VERSION 5.8 ;
BUSBITCHARS "[]" ;
DIVIDERCHAR "/" ;
UNITS
    DATABASE MICRONS 1000 ;
END UNITS

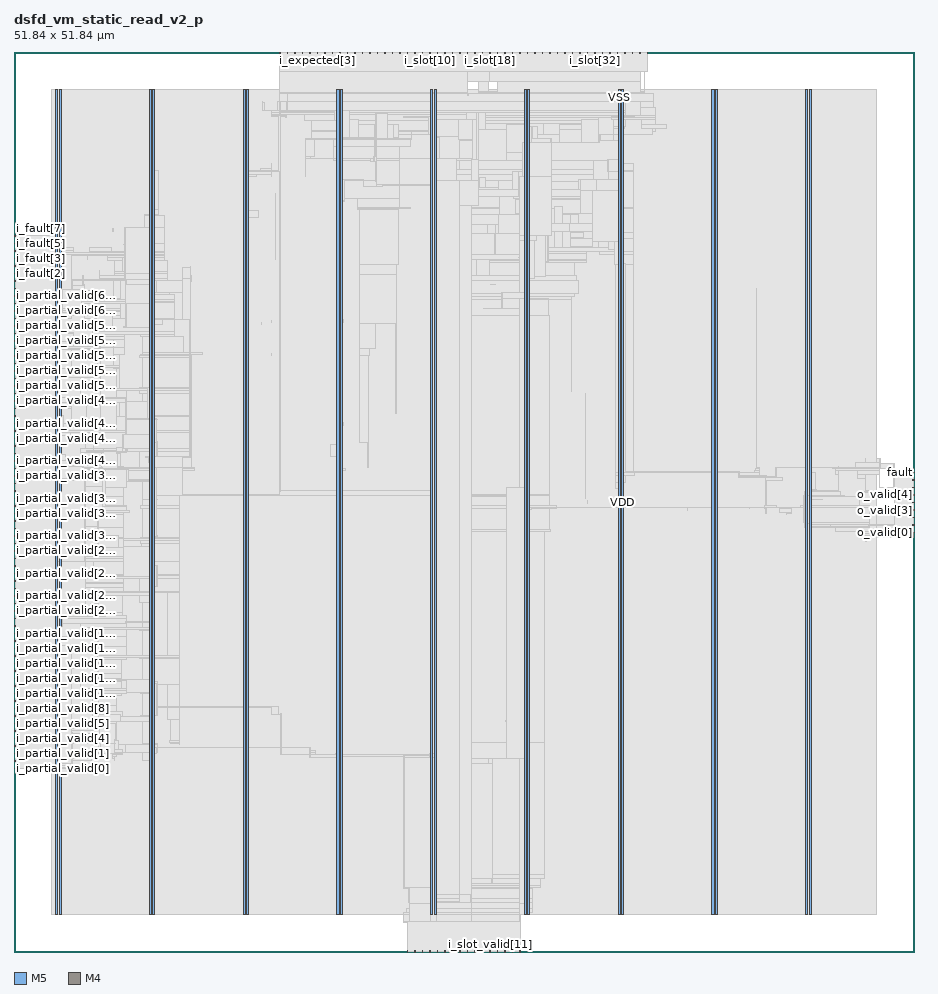
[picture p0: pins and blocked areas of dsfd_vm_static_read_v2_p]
MACRO dsfd_vm_static_read_v2_p
  FOREIGN dsfd_vm_static_read_v2_p 0 0 ;
  CLASS BLOCK ;
  SIZE 51.84 BY 51.84 ;
  PIN ck
    DIRECTION INPUT ;
    USE SIGNAL ;
    PORT
      LAYER M5 ;
        RECT  15.312 51.756 15.336 51.84 ;
    END
  END ck
  PIN fault
    DIRECTION OUTPUT ;
    USE SIGNAL ;
    PORT
      LAYER M4 ;
        RECT  51.756 27.6 51.84 27.624 ;
    END
  END fault
  PIN i_expected[0]
    DIRECTION INPUT ;
    USE SIGNAL ;
    PORT
      LAYER M5 ;
        RECT  16.176 51.756 16.2 51.84 ;
    END
  END i_expected[0]
  PIN i_expected[1]
    DIRECTION INPUT ;
    USE SIGNAL ;
    PORT
      LAYER M5 ;
        RECT  16.608 51.756 16.632 51.84 ;
    END
  END i_expected[1]
  PIN i_expected[2]
    DIRECTION INPUT ;
    USE SIGNAL ;
    PORT
      LAYER M5 ;
        RECT  17.04 51.756 17.064 51.84 ;
    END
  END i_expected[2]
  PIN i_expected[3]
    DIRECTION INPUT ;
    USE SIGNAL ;
    PORT
      LAYER M5 ;
        RECT  17.472 51.756 17.496 51.84 ;
    END
  END i_expected[3]
  PIN i_expected[4]
    DIRECTION INPUT ;
    USE SIGNAL ;
    PORT
      LAYER M5 ;
        RECT  17.904 51.756 17.928 51.84 ;
    END
  END i_expected[4]
  PIN i_expected[5]
    DIRECTION INPUT ;
    USE SIGNAL ;
    PORT
      LAYER M5 ;
        RECT  18.336 51.756 18.36 51.84 ;
    END
  END i_expected[5]
  PIN i_expected[6]
    DIRECTION INPUT ;
    USE SIGNAL ;
    PORT
      LAYER M5 ;
        RECT  18.768 51.756 18.792 51.84 ;
    END
  END i_expected[6]
  PIN i_expected[7]
    DIRECTION INPUT ;
    USE SIGNAL ;
    PORT
      LAYER M5 ;
        RECT  19.2 51.756 19.224 51.84 ;
    END
  END i_expected[7]
  PIN i_fault[0]
    DIRECTION INPUT ;
    USE SIGNAL ;
    PORT
      LAYER M4 ;
        RECT  0 38.208 0.084 38.232 ;
    END
  END i_fault[0]
  PIN i_fault[1]
    DIRECTION INPUT ;
    USE SIGNAL ;
    PORT
      LAYER M4 ;
        RECT  0 38.64 0.084 38.664 ;
    END
  END i_fault[1]
  PIN i_fault[2]
    DIRECTION INPUT ;
    USE SIGNAL ;
    PORT
      LAYER M4 ;
        RECT  0 39.072 0.084 39.096 ;
    END
  END i_fault[2]
  PIN i_fault[3]
    DIRECTION INPUT ;
    USE SIGNAL ;
    PORT
      LAYER M4 ;
        RECT  0 39.504 0.084 39.528 ;
    END
  END i_fault[3]
  PIN i_fault[4]
    DIRECTION INPUT ;
    USE SIGNAL ;
    PORT
      LAYER M4 ;
        RECT  0 39.936 0.084 39.96 ;
    END
  END i_fault[4]
  PIN i_fault[5]
    DIRECTION INPUT ;
    USE SIGNAL ;
    PORT
      LAYER M4 ;
        RECT  0 40.368 0.084 40.392 ;
    END
  END i_fault[5]
  PIN i_fault[6]
    DIRECTION INPUT ;
    USE SIGNAL ;
    PORT
      LAYER M4 ;
        RECT  0 40.8 0.084 40.824 ;
    END
  END i_fault[6]
  PIN i_fault[7]
    DIRECTION INPUT ;
    USE SIGNAL ;
    PORT
      LAYER M4 ;
        RECT  0 41.232 0.084 41.256 ;
    END
  END i_fault[7]
  PIN i_partial_valid[0]
    DIRECTION INPUT ;
    USE SIGNAL ;
    PORT
      LAYER M4 ;
        RECT  0 10.56 0.084 10.584 ;
    END
  END i_partial_valid[0]
  PIN i_partial_valid[10]
    DIRECTION INPUT ;
    USE SIGNAL ;
    PORT
      LAYER M4 ;
        RECT  0 14.88 0.084 14.904 ;
    END
  END i_partial_valid[10]
  PIN i_partial_valid[11]
    DIRECTION INPUT ;
    USE SIGNAL ;
    PORT
      LAYER M4 ;
        RECT  0 15.312 0.084 15.336 ;
    END
  END i_partial_valid[11]
  PIN i_partial_valid[12]
    DIRECTION INPUT ;
    USE SIGNAL ;
    PORT
      LAYER M4 ;
        RECT  0 15.744 0.084 15.768 ;
    END
  END i_partial_valid[12]
  PIN i_partial_valid[13]
    DIRECTION INPUT ;
    USE SIGNAL ;
    PORT
      LAYER M4 ;
        RECT  0 16.176 0.084 16.2 ;
    END
  END i_partial_valid[13]
  PIN i_partial_valid[14]
    DIRECTION INPUT ;
    USE SIGNAL ;
    PORT
      LAYER M4 ;
        RECT  0 16.608 0.084 16.632 ;
    END
  END i_partial_valid[14]
  PIN i_partial_valid[15]
    DIRECTION INPUT ;
    USE SIGNAL ;
    PORT
      LAYER M4 ;
        RECT  0 17.04 0.084 17.064 ;
    END
  END i_partial_valid[15]
  PIN i_partial_valid[16]
    DIRECTION INPUT ;
    USE SIGNAL ;
    PORT
      LAYER M4 ;
        RECT  0 17.472 0.084 17.496 ;
    END
  END i_partial_valid[16]
  PIN i_partial_valid[17]
    DIRECTION INPUT ;
    USE SIGNAL ;
    PORT
      LAYER M4 ;
        RECT  0 17.904 0.084 17.928 ;
    END
  END i_partial_valid[17]
  PIN i_partial_valid[18]
    DIRECTION INPUT ;
    USE SIGNAL ;
    PORT
      LAYER M4 ;
        RECT  0 18.336 0.084 18.36 ;
    END
  END i_partial_valid[18]
  PIN i_partial_valid[19]
    DIRECTION INPUT ;
    USE SIGNAL ;
    PORT
      LAYER M4 ;
        RECT  0 18.768 0.084 18.792 ;
    END
  END i_partial_valid[19]
  PIN i_partial_valid[1]
    DIRECTION INPUT ;
    USE SIGNAL ;
    PORT
      LAYER M4 ;
        RECT  0 10.992 0.084 11.016 ;
    END
  END i_partial_valid[1]
  PIN i_partial_valid[20]
    DIRECTION INPUT ;
    USE SIGNAL ;
    PORT
      LAYER M4 ;
        RECT  0 19.2 0.084 19.224 ;
    END
  END i_partial_valid[20]
  PIN i_partial_valid[21]
    DIRECTION INPUT ;
    USE SIGNAL ;
    PORT
      LAYER M4 ;
        RECT  0 19.632 0.084 19.656 ;
    END
  END i_partial_valid[21]
  PIN i_partial_valid[22]
    DIRECTION INPUT ;
    USE SIGNAL ;
    PORT
      LAYER M4 ;
        RECT  0 20.064 0.084 20.088 ;
    END
  END i_partial_valid[22]
  PIN i_partial_valid[23]
    DIRECTION INPUT ;
    USE SIGNAL ;
    PORT
      LAYER M4 ;
        RECT  0 20.496 0.084 20.52 ;
    END
  END i_partial_valid[23]
  PIN i_partial_valid[24]
    DIRECTION INPUT ;
    USE SIGNAL ;
    PORT
      LAYER M4 ;
        RECT  0 20.928 0.084 20.952 ;
    END
  END i_partial_valid[24]
  PIN i_partial_valid[25]
    DIRECTION INPUT ;
    USE SIGNAL ;
    PORT
      LAYER M4 ;
        RECT  0 21.36 0.084 21.384 ;
    END
  END i_partial_valid[25]
  PIN i_partial_valid[26]
    DIRECTION INPUT ;
    USE SIGNAL ;
    PORT
      LAYER M4 ;
        RECT  0 21.792 0.084 21.816 ;
    END
  END i_partial_valid[26]
  PIN i_partial_valid[27]
    DIRECTION INPUT ;
    USE SIGNAL ;
    PORT
      LAYER M4 ;
        RECT  0 22.224 0.084 22.248 ;
    END
  END i_partial_valid[27]
  PIN i_partial_valid[28]
    DIRECTION INPUT ;
    USE SIGNAL ;
    PORT
      LAYER M4 ;
        RECT  0 22.656 0.084 22.68 ;
    END
  END i_partial_valid[28]
  PIN i_partial_valid[29]
    DIRECTION INPUT ;
    USE SIGNAL ;
    PORT
      LAYER M4 ;
        RECT  0 23.088 0.084 23.112 ;
    END
  END i_partial_valid[29]
  PIN i_partial_valid[2]
    DIRECTION INPUT ;
    USE SIGNAL ;
    PORT
      LAYER M4 ;
        RECT  0 11.424 0.084 11.448 ;
    END
  END i_partial_valid[2]
  PIN i_partial_valid[30]
    DIRECTION INPUT ;
    USE SIGNAL ;
    PORT
      LAYER M4 ;
        RECT  0 23.52 0.084 23.544 ;
    END
  END i_partial_valid[30]
  PIN i_partial_valid[31]
    DIRECTION INPUT ;
    USE SIGNAL ;
    PORT
      LAYER M4 ;
        RECT  0 23.952 0.084 23.976 ;
    END
  END i_partial_valid[31]
  PIN i_partial_valid[32]
    DIRECTION INPUT ;
    USE SIGNAL ;
    PORT
      LAYER M4 ;
        RECT  0 24.384 0.084 24.408 ;
    END
  END i_partial_valid[32]
  PIN i_partial_valid[33]
    DIRECTION INPUT ;
    USE SIGNAL ;
    PORT
      LAYER M4 ;
        RECT  0 24.816 0.084 24.84 ;
    END
  END i_partial_valid[33]
  PIN i_partial_valid[34]
    DIRECTION INPUT ;
    USE SIGNAL ;
    PORT
      LAYER M4 ;
        RECT  0 25.248 0.084 25.272 ;
    END
  END i_partial_valid[34]
  PIN i_partial_valid[35]
    DIRECTION INPUT ;
    USE SIGNAL ;
    PORT
      LAYER M4 ;
        RECT  0 25.68 0.084 25.704 ;
    END
  END i_partial_valid[35]
  PIN i_partial_valid[36]
    DIRECTION INPUT ;
    USE SIGNAL ;
    PORT
      LAYER M4 ;
        RECT  0 26.112 0.084 26.136 ;
    END
  END i_partial_valid[36]
  PIN i_partial_valid[37]
    DIRECTION INPUT ;
    USE SIGNAL ;
    PORT
      LAYER M4 ;
        RECT  0 26.544 0.084 26.568 ;
    END
  END i_partial_valid[37]
  PIN i_partial_valid[38]
    DIRECTION INPUT ;
    USE SIGNAL ;
    PORT
      LAYER M4 ;
        RECT  0 26.976 0.084 27 ;
    END
  END i_partial_valid[38]
  PIN i_partial_valid[39]
    DIRECTION INPUT ;
    USE SIGNAL ;
    PORT
      LAYER M4 ;
        RECT  0 27.408 0.084 27.432 ;
    END
  END i_partial_valid[39]
  PIN i_partial_valid[3]
    DIRECTION INPUT ;
    USE SIGNAL ;
    PORT
      LAYER M4 ;
        RECT  0 11.856 0.084 11.88 ;
    END
  END i_partial_valid[3]
  PIN i_partial_valid[40]
    DIRECTION INPUT ;
    USE SIGNAL ;
    PORT
      LAYER M4 ;
        RECT  0 27.84 0.084 27.864 ;
    END
  END i_partial_valid[40]
  PIN i_partial_valid[41]
    DIRECTION INPUT ;
    USE SIGNAL ;
    PORT
      LAYER M4 ;
        RECT  0 28.272 0.084 28.296 ;
    END
  END i_partial_valid[41]
  PIN i_partial_valid[42]
    DIRECTION INPUT ;
    USE SIGNAL ;
    PORT
      LAYER M4 ;
        RECT  0 28.704 0.084 28.728 ;
    END
  END i_partial_valid[42]
  PIN i_partial_valid[43]
    DIRECTION INPUT ;
    USE SIGNAL ;
    PORT
      LAYER M4 ;
        RECT  0 29.136 0.084 29.16 ;
    END
  END i_partial_valid[43]
  PIN i_partial_valid[44]
    DIRECTION INPUT ;
    USE SIGNAL ;
    PORT
      LAYER M4 ;
        RECT  0 29.568 0.084 29.592 ;
    END
  END i_partial_valid[44]
  PIN i_partial_valid[45]
    DIRECTION INPUT ;
    USE SIGNAL ;
    PORT
      LAYER M4 ;
        RECT  0 30 0.084 30.024 ;
    END
  END i_partial_valid[45]
  PIN i_partial_valid[46]
    DIRECTION INPUT ;
    USE SIGNAL ;
    PORT
      LAYER M4 ;
        RECT  0 30.432 0.084 30.456 ;
    END
  END i_partial_valid[46]
  PIN i_partial_valid[47]
    DIRECTION INPUT ;
    USE SIGNAL ;
    PORT
      LAYER M4 ;
        RECT  0 30.864 0.084 30.888 ;
    END
  END i_partial_valid[47]
  PIN i_partial_valid[48]
    DIRECTION INPUT ;
    USE SIGNAL ;
    PORT
      LAYER M4 ;
        RECT  0 31.296 0.084 31.32 ;
    END
  END i_partial_valid[48]
  PIN i_partial_valid[49]
    DIRECTION INPUT ;
    USE SIGNAL ;
    PORT
      LAYER M4 ;
        RECT  0 31.728 0.084 31.752 ;
    END
  END i_partial_valid[49]
  PIN i_partial_valid[4]
    DIRECTION INPUT ;
    USE SIGNAL ;
    PORT
      LAYER M4 ;
        RECT  0 12.288 0.084 12.312 ;
    END
  END i_partial_valid[4]
  PIN i_partial_valid[50]
    DIRECTION INPUT ;
    USE SIGNAL ;
    PORT
      LAYER M4 ;
        RECT  0 32.16 0.084 32.184 ;
    END
  END i_partial_valid[50]
  PIN i_partial_valid[51]
    DIRECTION INPUT ;
    USE SIGNAL ;
    PORT
      LAYER M4 ;
        RECT  0 32.592 0.084 32.616 ;
    END
  END i_partial_valid[51]
  PIN i_partial_valid[52]
    DIRECTION INPUT ;
    USE SIGNAL ;
    PORT
      LAYER M4 ;
        RECT  0 33.024 0.084 33.048 ;
    END
  END i_partial_valid[52]
  PIN i_partial_valid[53]
    DIRECTION INPUT ;
    USE SIGNAL ;
    PORT
      LAYER M4 ;
        RECT  0 33.456 0.084 33.48 ;
    END
  END i_partial_valid[53]
  PIN i_partial_valid[54]
    DIRECTION INPUT ;
    USE SIGNAL ;
    PORT
      LAYER M4 ;
        RECT  0 33.888 0.084 33.912 ;
    END
  END i_partial_valid[54]
  PIN i_partial_valid[55]
    DIRECTION INPUT ;
    USE SIGNAL ;
    PORT
      LAYER M4 ;
        RECT  0 34.32 0.084 34.344 ;
    END
  END i_partial_valid[55]
  PIN i_partial_valid[56]
    DIRECTION INPUT ;
    USE SIGNAL ;
    PORT
      LAYER M4 ;
        RECT  0 34.752 0.084 34.776 ;
    END
  END i_partial_valid[56]
  PIN i_partial_valid[57]
    DIRECTION INPUT ;
    USE SIGNAL ;
    PORT
      LAYER M4 ;
        RECT  0 35.184 0.084 35.208 ;
    END
  END i_partial_valid[57]
  PIN i_partial_valid[58]
    DIRECTION INPUT ;
    USE SIGNAL ;
    PORT
      LAYER M4 ;
        RECT  0 35.616 0.084 35.64 ;
    END
  END i_partial_valid[58]
  PIN i_partial_valid[59]
    DIRECTION INPUT ;
    USE SIGNAL ;
    PORT
      LAYER M4 ;
        RECT  0 36.048 0.084 36.072 ;
    END
  END i_partial_valid[59]
  PIN i_partial_valid[5]
    DIRECTION INPUT ;
    USE SIGNAL ;
    PORT
      LAYER M4 ;
        RECT  0 12.72 0.084 12.744 ;
    END
  END i_partial_valid[5]
  PIN i_partial_valid[60]
    DIRECTION INPUT ;
    USE SIGNAL ;
    PORT
      LAYER M4 ;
        RECT  0 36.48 0.084 36.504 ;
    END
  END i_partial_valid[60]
  PIN i_partial_valid[61]
    DIRECTION INPUT ;
    USE SIGNAL ;
    PORT
      LAYER M4 ;
        RECT  0 36.912 0.084 36.936 ;
    END
  END i_partial_valid[61]
  PIN i_partial_valid[62]
    DIRECTION INPUT ;
    USE SIGNAL ;
    PORT
      LAYER M4 ;
        RECT  0 37.344 0.084 37.368 ;
    END
  END i_partial_valid[62]
  PIN i_partial_valid[63]
    DIRECTION INPUT ;
    USE SIGNAL ;
    PORT
      LAYER M4 ;
        RECT  0 37.776 0.084 37.8 ;
    END
  END i_partial_valid[63]
  PIN i_partial_valid[6]
    DIRECTION INPUT ;
    USE SIGNAL ;
    PORT
      LAYER M4 ;
        RECT  0 13.152 0.084 13.176 ;
    END
  END i_partial_valid[6]
  PIN i_partial_valid[7]
    DIRECTION INPUT ;
    USE SIGNAL ;
    PORT
      LAYER M4 ;
        RECT  0 13.584 0.084 13.608 ;
    END
  END i_partial_valid[7]
  PIN i_partial_valid[8]
    DIRECTION INPUT ;
    USE SIGNAL ;
    PORT
      LAYER M4 ;
        RECT  0 14.016 0.084 14.04 ;
    END
  END i_partial_valid[8]
  PIN i_partial_valid[9]
    DIRECTION INPUT ;
    USE SIGNAL ;
    PORT
      LAYER M4 ;
        RECT  0 14.448 0.084 14.472 ;
    END
  END i_partial_valid[9]
  PIN i_slot[0]
    DIRECTION INPUT ;
    USE SIGNAL ;
    PORT
      LAYER M5 ;
        RECT  19.632 51.756 19.656 51.84 ;
    END
  END i_slot[0]
  PIN i_slot[10]
    DIRECTION INPUT ;
    USE SIGNAL ;
    PORT
      LAYER M5 ;
        RECT  23.952 51.756 23.976 51.84 ;
    END
  END i_slot[10]
  PIN i_slot[11]
    DIRECTION INPUT ;
    USE SIGNAL ;
    PORT
      LAYER M5 ;
        RECT  24.384 51.756 24.408 51.84 ;
    END
  END i_slot[11]
  PIN i_slot[12]
    DIRECTION INPUT ;
    USE SIGNAL ;
    PORT
      LAYER M5 ;
        RECT  24.816 51.756 24.84 51.84 ;
    END
  END i_slot[12]
  PIN i_slot[13]
    DIRECTION INPUT ;
    USE SIGNAL ;
    PORT
      LAYER M5 ;
        RECT  25.248 51.756 25.272 51.84 ;
    END
  END i_slot[13]
  PIN i_slot[14]
    DIRECTION INPUT ;
    USE SIGNAL ;
    PORT
      LAYER M5 ;
        RECT  25.68 51.756 25.704 51.84 ;
    END
  END i_slot[14]
  PIN i_slot[15]
    DIRECTION INPUT ;
    USE SIGNAL ;
    PORT
      LAYER M5 ;
        RECT  26.112 51.756 26.136 51.84 ;
    END
  END i_slot[15]
  PIN i_slot[16]
    DIRECTION INPUT ;
    USE SIGNAL ;
    PORT
      LAYER M5 ;
        RECT  26.544 51.756 26.568 51.84 ;
    END
  END i_slot[16]
  PIN i_slot[17]
    DIRECTION INPUT ;
    USE SIGNAL ;
    PORT
      LAYER M5 ;
        RECT  26.976 51.756 27 51.84 ;
    END
  END i_slot[17]
  PIN i_slot[18]
    DIRECTION INPUT ;
    USE SIGNAL ;
    PORT
      LAYER M5 ;
        RECT  27.408 51.756 27.432 51.84 ;
    END
  END i_slot[18]
  PIN i_slot[19]
    DIRECTION INPUT ;
    USE SIGNAL ;
    PORT
      LAYER M5 ;
        RECT  27.84 51.756 27.864 51.84 ;
    END
  END i_slot[19]
  PIN i_slot[1]
    DIRECTION INPUT ;
    USE SIGNAL ;
    PORT
      LAYER M5 ;
        RECT  20.064 51.756 20.088 51.84 ;
    END
  END i_slot[1]
  PIN i_slot[20]
    DIRECTION INPUT ;
    USE SIGNAL ;
    PORT
      LAYER M5 ;
        RECT  28.272 51.756 28.296 51.84 ;
    END
  END i_slot[20]
  PIN i_slot[21]
    DIRECTION INPUT ;
    USE SIGNAL ;
    PORT
      LAYER M5 ;
        RECT  28.704 51.756 28.728 51.84 ;
    END
  END i_slot[21]
  PIN i_slot[22]
    DIRECTION INPUT ;
    USE SIGNAL ;
    PORT
      LAYER M5 ;
        RECT  29.136 51.756 29.16 51.84 ;
    END
  END i_slot[22]
  PIN i_slot[23]
    DIRECTION INPUT ;
    USE SIGNAL ;
    PORT
      LAYER M5 ;
        RECT  29.568 51.756 29.592 51.84 ;
    END
  END i_slot[23]
  PIN i_slot[24]
    DIRECTION INPUT ;
    USE SIGNAL ;
    PORT
      LAYER M5 ;
        RECT  30 51.756 30.024 51.84 ;
    END
  END i_slot[24]
  PIN i_slot[25]
    DIRECTION INPUT ;
    USE SIGNAL ;
    PORT
      LAYER M5 ;
        RECT  30.432 51.756 30.456 51.84 ;
    END
  END i_slot[25]
  PIN i_slot[26]
    DIRECTION INPUT ;
    USE SIGNAL ;
    PORT
      LAYER M5 ;
        RECT  30.864 51.756 30.888 51.84 ;
    END
  END i_slot[26]
  PIN i_slot[27]
    DIRECTION INPUT ;
    USE SIGNAL ;
    PORT
      LAYER M5 ;
        RECT  31.296 51.756 31.32 51.84 ;
    END
  END i_slot[27]
  PIN i_slot[28]
    DIRECTION INPUT ;
    USE SIGNAL ;
    PORT
      LAYER M5 ;
        RECT  31.728 51.756 31.752 51.84 ;
    END
  END i_slot[28]
  PIN i_slot[29]
    DIRECTION INPUT ;
    USE SIGNAL ;
    PORT
      LAYER M5 ;
        RECT  32.16 51.756 32.184 51.84 ;
    END
  END i_slot[29]
  PIN i_slot[2]
    DIRECTION INPUT ;
    USE SIGNAL ;
    PORT
      LAYER M5 ;
        RECT  20.496 51.756 20.52 51.84 ;
    END
  END i_slot[2]
  PIN i_slot[30]
    DIRECTION INPUT ;
    USE SIGNAL ;
    PORT
      LAYER M5 ;
        RECT  32.592 51.756 32.616 51.84 ;
    END
  END i_slot[30]
  PIN i_slot[31]
    DIRECTION INPUT ;
    USE SIGNAL ;
    PORT
      LAYER M5 ;
        RECT  33.024 51.756 33.048 51.84 ;
    END
  END i_slot[31]
  PIN i_slot[32]
    DIRECTION INPUT ;
    USE SIGNAL ;
    PORT
      LAYER M5 ;
        RECT  33.456 51.756 33.48 51.84 ;
    END
  END i_slot[32]
  PIN i_slot[33]
    DIRECTION INPUT ;
    USE SIGNAL ;
    PORT
      LAYER M5 ;
        RECT  33.888 51.756 33.912 51.84 ;
    END
  END i_slot[33]
  PIN i_slot[34]
    DIRECTION INPUT ;
    USE SIGNAL ;
    PORT
      LAYER M5 ;
        RECT  34.32 51.756 34.344 51.84 ;
    END
  END i_slot[34]
  PIN i_slot[35]
    DIRECTION INPUT ;
    USE SIGNAL ;
    PORT
      LAYER M5 ;
        RECT  34.752 51.756 34.776 51.84 ;
    END
  END i_slot[35]
  PIN i_slot[36]
    DIRECTION INPUT ;
    USE SIGNAL ;
    PORT
      LAYER M5 ;
        RECT  35.184 51.756 35.208 51.84 ;
    END
  END i_slot[36]
  PIN i_slot[37]
    DIRECTION INPUT ;
    USE SIGNAL ;
    PORT
      LAYER M5 ;
        RECT  35.616 51.756 35.64 51.84 ;
    END
  END i_slot[37]
  PIN i_slot[38]
    DIRECTION INPUT ;
    USE SIGNAL ;
    PORT
      LAYER M5 ;
        RECT  36.048 51.756 36.072 51.84 ;
    END
  END i_slot[38]
  PIN i_slot[39]
    DIRECTION INPUT ;
    USE SIGNAL ;
    PORT
      LAYER M5 ;
        RECT  36.48 51.756 36.504 51.84 ;
    END
  END i_slot[39]
  PIN i_slot[3]
    DIRECTION INPUT ;
    USE SIGNAL ;
    PORT
      LAYER M5 ;
        RECT  20.928 51.756 20.952 51.84 ;
    END
  END i_slot[3]
  PIN i_slot[4]
    DIRECTION INPUT ;
    USE SIGNAL ;
    PORT
      LAYER M5 ;
        RECT  21.36 51.756 21.384 51.84 ;
    END
  END i_slot[4]
  PIN i_slot[5]
    DIRECTION INPUT ;
    USE SIGNAL ;
    PORT
      LAYER M5 ;
        RECT  21.792 51.756 21.816 51.84 ;
    END
  END i_slot[5]
  PIN i_slot[6]
    DIRECTION INPUT ;
    USE SIGNAL ;
    PORT
      LAYER M5 ;
        RECT  22.224 51.756 22.248 51.84 ;
    END
  END i_slot[6]
  PIN i_slot[7]
    DIRECTION INPUT ;
    USE SIGNAL ;
    PORT
      LAYER M5 ;
        RECT  22.656 51.756 22.68 51.84 ;
    END
  END i_slot[7]
  PIN i_slot[8]
    DIRECTION INPUT ;
    USE SIGNAL ;
    PORT
      LAYER M5 ;
        RECT  23.088 51.756 23.112 51.84 ;
    END
  END i_slot[8]
  PIN i_slot[9]
    DIRECTION INPUT ;
    USE SIGNAL ;
    PORT
      LAYER M5 ;
        RECT  23.52 51.756 23.544 51.84 ;
    END
  END i_slot[9]
  PIN i_slot_valid[0]
    DIRECTION INPUT ;
    USE SIGNAL ;
    PORT
      LAYER M5 ;
        RECT  22.656 0 22.68 0.084 ;
    END
  END i_slot_valid[0]
  PIN i_slot_valid[10]
    DIRECTION INPUT ;
    USE SIGNAL ;
    PORT
      LAYER M5 ;
        RECT  26.976 0 27 0.084 ;
    END
  END i_slot_valid[10]
  PIN i_slot_valid[11]
    DIRECTION INPUT ;
    USE SIGNAL ;
    PORT
      LAYER M5 ;
        RECT  27.408 0 27.432 0.084 ;
    END
  END i_slot_valid[11]
  PIN i_slot_valid[12]
    DIRECTION INPUT ;
    USE SIGNAL ;
    PORT
      LAYER M5 ;
        RECT  27.84 0 27.864 0.084 ;
    END
  END i_slot_valid[12]
  PIN i_slot_valid[13]
    DIRECTION INPUT ;
    USE SIGNAL ;
    PORT
      LAYER M5 ;
        RECT  28.272 0 28.296 0.084 ;
    END
  END i_slot_valid[13]
  PIN i_slot_valid[14]
    DIRECTION INPUT ;
    USE SIGNAL ;
    PORT
      LAYER M5 ;
        RECT  28.704 0 28.728 0.084 ;
    END
  END i_slot_valid[14]
  PIN i_slot_valid[15]
    DIRECTION INPUT ;
    USE SIGNAL ;
    PORT
      LAYER M5 ;
        RECT  29.136 0 29.16 0.084 ;
    END
  END i_slot_valid[15]
  PIN i_slot_valid[1]
    DIRECTION INPUT ;
    USE SIGNAL ;
    PORT
      LAYER M5 ;
        RECT  23.088 0 23.112 0.084 ;
    END
  END i_slot_valid[1]
  PIN i_slot_valid[2]
    DIRECTION INPUT ;
    USE SIGNAL ;
    PORT
      LAYER M5 ;
        RECT  23.52 0 23.544 0.084 ;
    END
  END i_slot_valid[2]
  PIN i_slot_valid[3]
    DIRECTION INPUT ;
    USE SIGNAL ;
    PORT
      LAYER M5 ;
        RECT  23.952 0 23.976 0.084 ;
    END
  END i_slot_valid[3]
  PIN i_slot_valid[4]
    DIRECTION INPUT ;
    USE SIGNAL ;
    PORT
      LAYER M5 ;
        RECT  24.384 0 24.408 0.084 ;
    END
  END i_slot_valid[4]
  PIN i_slot_valid[5]
    DIRECTION INPUT ;
    USE SIGNAL ;
    PORT
      LAYER M5 ;
        RECT  24.816 0 24.84 0.084 ;
    END
  END i_slot_valid[5]
  PIN i_slot_valid[6]
    DIRECTION INPUT ;
    USE SIGNAL ;
    PORT
      LAYER M5 ;
        RECT  25.248 0 25.272 0.084 ;
    END
  END i_slot_valid[6]
  PIN i_slot_valid[7]
    DIRECTION INPUT ;
    USE SIGNAL ;
    PORT
      LAYER M5 ;
        RECT  25.68 0 25.704 0.084 ;
    END
  END i_slot_valid[7]
  PIN i_slot_valid[8]
    DIRECTION INPUT ;
    USE SIGNAL ;
    PORT
      LAYER M5 ;
        RECT  26.112 0 26.136 0.084 ;
    END
  END i_slot_valid[8]
  PIN i_slot_valid[9]
    DIRECTION INPUT ;
    USE SIGNAL ;
    PORT
      LAYER M5 ;
        RECT  26.544 0 26.568 0.084 ;
    END
  END i_slot_valid[9]
  PIN o_valid[0]
    DIRECTION OUTPUT ;
    USE SIGNAL ;
    PORT
      LAYER M4 ;
        RECT  51.756 24.144 51.84 24.168 ;
    END
  END o_valid[0]
  PIN o_valid[1]
    DIRECTION OUTPUT ;
    USE SIGNAL ;
    PORT
      LAYER M4 ;
        RECT  51.756 24.576 51.84 24.6 ;
    END
  END o_valid[1]
  PIN o_valid[2]
    DIRECTION OUTPUT ;
    USE SIGNAL ;
    PORT
      LAYER M4 ;
        RECT  51.756 25.008 51.84 25.032 ;
    END
  END o_valid[2]
  PIN o_valid[3]
    DIRECTION OUTPUT ;
    USE SIGNAL ;
    PORT
      LAYER M4 ;
        RECT  51.756 25.44 51.84 25.464 ;
    END
  END o_valid[3]
  PIN o_valid[4]
    DIRECTION OUTPUT ;
    USE SIGNAL ;
    PORT
      LAYER M4 ;
        RECT  51.756 25.872 51.84 25.896 ;
    END
  END o_valid[4]
  PIN o_valid[5]
    DIRECTION OUTPUT ;
    USE SIGNAL ;
    PORT
      LAYER M4 ;
        RECT  51.756 26.304 51.84 26.328 ;
    END
  END o_valid[5]
  PIN o_valid[6]
    DIRECTION OUTPUT ;
    USE SIGNAL ;
    PORT
      LAYER M4 ;
        RECT  51.756 26.736 51.84 26.76 ;
    END
  END o_valid[6]
  PIN o_valid[7]
    DIRECTION OUTPUT ;
    USE SIGNAL ;
    PORT
      LAYER M4 ;
        RECT  51.756 27.168 51.84 27.192 ;
    END
  END o_valid[7]
  PIN rst_n
    DIRECTION INPUT ;
    USE SIGNAL ;
    PORT
      LAYER M5 ;
        RECT  15.744 51.756 15.768 51.84 ;
    END
  END rst_n
  PIN VDD
    DIRECTION INOUT ;
    USE POWER ;
    PORT
      LAYER M5 ;
        RECT  45.792 2.151 45.912 49.689 ;
        RECT  40.392 2.151 40.512 49.689 ;
        RECT  34.992 2.151 35.112 49.689 ;
        RECT  29.592 2.151 29.712 49.689 ;
        RECT  24.192 2.151 24.312 49.689 ;
        RECT  18.792 2.151 18.912 49.689 ;
        RECT  13.392 2.151 13.512 49.689 ;
        RECT  7.992 2.151 8.112 49.689 ;
        RECT  2.592 2.151 2.712 49.689 ;
    END
  END VDD
  PIN VSS
    DIRECTION INOUT ;
    USE GROUND ;
    PORT
      LAYER M5 ;
        RECT  45.6 2.137 45.72 49.703 ;
        RECT  40.2 2.137 40.32 49.703 ;
        RECT  34.8 2.137 34.92 49.703 ;
        RECT  29.4 2.137 29.52 49.703 ;
        RECT  24 2.137 24.12 49.703 ;
        RECT  18.6 2.137 18.72 49.703 ;
        RECT  13.2 2.137 13.32 49.703 ;
        RECT  7.8 2.137 7.92 49.703 ;
        RECT  2.4 2.137 2.52 49.703 ;
    END
  END VSS
  # OT_OBS_CLOSED layer=M5 d_um=1.536 added=40
  OBS
    LAYER RVTN ;
     RECT  2.16 2.16 49.68 2.295 ;
     RECT  2.16 2.565 49.68 2.835 ;
     RECT  2.16 3.105 49.68 3.375 ;
     RECT  2.16 3.645 49.68 3.915 ;
     RECT  2.16 4.185 49.68 4.455 ;
     RECT  2.16 4.725 49.68 4.995 ;
     RECT  2.16 5.265 49.68 5.535 ;
     RECT  2.16 5.805 49.68 6.075 ;
     RECT  2.16 6.345 49.68 6.615 ;
     RECT  2.16 6.885 49.68 7.155 ;
     RECT  2.16 7.425 49.68 7.695 ;
     RECT  2.16 7.965 49.68 8.235 ;
     RECT  2.16 8.505 49.68 8.775 ;
     RECT  2.16 9.045 49.68 9.315 ;
     RECT  2.16 9.585 49.68 9.855 ;
     RECT  2.16 10.125 49.68 10.395 ;
     RECT  2.16 10.665 49.68 10.935 ;
     RECT  2.16 11.205 49.68 11.475 ;
     RECT  2.16 11.745 49.68 12.015 ;
     RECT  2.16 12.285 49.68 12.555 ;
     RECT  2.16 12.825 49.68 13.095 ;
     RECT  2.16 13.365 49.68 13.635 ;
     RECT  2.16 13.905 49.68 14.175 ;
     RECT  2.16 14.445 49.68 14.715 ;
     RECT  2.16 14.985 49.68 15.255 ;
     RECT  2.16 15.525 49.68 15.795 ;
     RECT  2.16 16.065 49.68 16.335 ;
     RECT  2.16 16.605 49.68 16.875 ;
     RECT  2.16 17.145 49.68 17.415 ;
     RECT  2.16 17.685 49.68 17.955 ;
     RECT  2.16 18.225 49.68 18.495 ;
     RECT  2.16 18.765 49.68 19.035 ;
     RECT  2.16 19.305 49.68 19.575 ;
     RECT  2.16 19.845 49.68 20.115 ;
     RECT  2.16 20.385 49.68 20.655 ;
     RECT  2.16 20.925 49.68 21.195 ;
     RECT  2.16 21.465 49.68 21.735 ;
     RECT  2.16 22.005 49.68 22.275 ;
     RECT  2.16 22.545 49.68 22.815 ;
     RECT  2.16 23.085 49.68 23.355 ;
     RECT  2.16 23.625 49.68 23.895 ;
     RECT  2.16 24.165 49.68 24.435 ;
     RECT  2.16 24.705 49.68 24.975 ;
     RECT  2.16 25.245 49.68 25.515 ;
     RECT  2.16 25.785 49.68 26.055 ;
     RECT  2.16 26.325 49.68 26.595 ;
     RECT  2.16 26.865 49.68 27.135 ;
     RECT  2.16 27.405 49.68 27.675 ;
     RECT  2.16 27.945 49.68 28.215 ;
     RECT  2.16 28.485 49.68 28.755 ;
     RECT  2.16 29.025 49.68 29.295 ;
     RECT  2.16 29.565 49.68 29.835 ;
     RECT  2.16 30.105 49.68 30.375 ;
     RECT  2.16 30.645 49.68 30.915 ;
     RECT  2.16 31.185 49.68 31.455 ;
     RECT  2.16 31.725 49.68 31.995 ;
     RECT  2.16 32.265 49.68 32.535 ;
     RECT  2.16 32.805 49.68 33.075 ;
     RECT  2.16 33.345 49.68 33.615 ;
     RECT  2.16 33.885 49.68 34.155 ;
     RECT  2.16 34.425 49.68 34.695 ;
     RECT  2.16 34.965 49.68 35.235 ;
     RECT  2.16 35.505 49.68 35.775 ;
     RECT  2.16 36.045 49.68 36.315 ;
     RECT  2.16 36.585 49.68 36.855 ;
     RECT  2.16 37.125 49.68 37.395 ;
     RECT  2.16 37.665 49.68 37.935 ;
     RECT  2.16 38.205 49.68 38.475 ;
     RECT  2.16 38.745 49.68 39.015 ;
     RECT  2.16 39.285 49.68 39.555 ;
     RECT  2.16 39.825 49.68 40.095 ;
     RECT  2.16 40.365 49.68 40.635 ;
     RECT  2.16 40.905 49.68 41.175 ;
     RECT  2.16 41.445 49.68 41.715 ;
     RECT  2.16 41.985 49.68 42.255 ;
     RECT  2.16 42.525 49.68 42.795 ;
     RECT  2.16 43.065 49.68 43.335 ;
     RECT  2.16 43.605 49.68 43.875 ;
     RECT  2.16 44.145 49.68 44.415 ;
     RECT  2.16 44.685 49.68 44.955 ;
     RECT  2.16 45.225 49.68 45.495 ;
     RECT  2.16 45.765 49.68 46.035 ;
     RECT  2.16 46.305 49.68 46.575 ;
     RECT  2.16 46.845 49.68 47.115 ;
     RECT  2.16 47.385 49.68 47.655 ;
     RECT  2.16 47.925 49.68 48.195 ;
     RECT  2.16 48.465 49.68 48.735 ;
     RECT  2.16 49.005 49.68 49.275 ;
     RECT  2.16 49.545 49.68 49.68 ;
    LAYER RVTP ;
     RECT  2.16 2.295 49.68 2.565 ;
     RECT  2.16 2.835 49.68 3.105 ;
     RECT  2.16 3.375 49.68 3.645 ;
     RECT  2.16 3.915 49.68 4.185 ;
     RECT  2.16 4.455 49.68 4.725 ;
     RECT  2.16 4.995 49.68 5.265 ;
     RECT  2.16 5.535 49.68 5.805 ;
     RECT  2.16 6.075 49.68 6.345 ;
     RECT  2.16 6.615 49.68 6.885 ;
     RECT  2.16 7.155 49.68 7.425 ;
     RECT  2.16 7.695 49.68 7.965 ;
     RECT  2.16 8.235 49.68 8.505 ;
     RECT  2.16 8.775 49.68 9.045 ;
     RECT  2.16 9.315 49.68 9.585 ;
     RECT  2.16 9.855 49.68 10.125 ;
     RECT  2.16 10.395 49.68 10.665 ;
     RECT  2.16 10.935 49.68 11.205 ;
     RECT  2.16 11.475 49.68 11.745 ;
     RECT  2.16 12.015 49.68 12.285 ;
     RECT  2.16 12.555 49.68 12.825 ;
     RECT  2.16 13.095 49.68 13.365 ;
     RECT  2.16 13.635 49.68 13.905 ;
     RECT  2.16 14.175 49.68 14.445 ;
     RECT  2.16 14.715 49.68 14.985 ;
     RECT  2.16 15.255 49.68 15.525 ;
     RECT  2.16 15.795 49.68 16.065 ;
     RECT  2.16 16.335 49.68 16.605 ;
     RECT  2.16 16.875 49.68 17.145 ;
     RECT  2.16 17.415 49.68 17.685 ;
     RECT  2.16 17.955 49.68 18.225 ;
     RECT  2.16 18.495 49.68 18.765 ;
     RECT  2.16 19.035 49.68 19.305 ;
     RECT  2.16 19.575 49.68 19.845 ;
     RECT  2.16 20.115 49.68 20.385 ;
     RECT  2.16 20.655 49.68 20.925 ;
     RECT  2.16 21.195 49.68 21.465 ;
     RECT  2.16 21.735 49.68 22.005 ;
     RECT  2.16 22.275 49.68 22.545 ;
     RECT  2.16 22.815 49.68 23.085 ;
     RECT  2.16 23.355 49.68 23.625 ;
     RECT  2.16 23.895 49.68 24.165 ;
     RECT  2.16 24.435 49.68 24.705 ;
     RECT  2.16 24.975 49.68 25.245 ;
     RECT  2.16 25.515 49.68 25.785 ;
     RECT  2.16 26.055 49.68 26.325 ;
     RECT  2.16 26.595 49.68 26.865 ;
     RECT  2.16 27.135 49.68 27.405 ;
     RECT  2.16 27.675 49.68 27.945 ;
     RECT  2.16 28.215 49.68 28.485 ;
     RECT  2.16 28.755 49.68 29.025 ;
     RECT  2.16 29.295 49.68 29.565 ;
     RECT  2.16 29.835 49.68 30.105 ;
     RECT  2.16 30.375 49.68 30.645 ;
     RECT  2.16 30.915 49.68 31.185 ;
     RECT  2.16 31.455 49.68 31.725 ;
     RECT  2.16 31.995 49.68 32.265 ;
     RECT  2.16 32.535 49.68 32.805 ;
     RECT  2.16 33.075 49.68 33.345 ;
     RECT  2.16 33.615 49.68 33.885 ;
     RECT  2.16 34.155 49.68 34.425 ;
     RECT  2.16 34.695 49.68 34.965 ;
     RECT  2.16 35.235 49.68 35.505 ;
     RECT  2.16 35.775 49.68 36.045 ;
     RECT  2.16 36.315 49.68 36.585 ;
     RECT  2.16 36.855 49.68 37.125 ;
     RECT  2.16 37.395 49.68 37.665 ;
     RECT  2.16 37.935 49.68 38.205 ;
     RECT  2.16 38.475 49.68 38.745 ;
     RECT  2.16 39.015 49.68 39.285 ;
     RECT  2.16 39.555 49.68 39.825 ;
     RECT  2.16 40.095 49.68 40.365 ;
     RECT  2.16 40.635 49.68 40.905 ;
     RECT  2.16 41.175 49.68 41.445 ;
     RECT  2.16 41.715 49.68 41.985 ;
     RECT  2.16 42.255 49.68 42.525 ;
     RECT  2.16 42.795 49.68 43.065 ;
     RECT  2.16 43.335 49.68 43.605 ;
     RECT  2.16 43.875 49.68 44.145 ;
     RECT  2.16 44.415 49.68 44.685 ;
     RECT  2.16 44.955 49.68 45.225 ;
     RECT  2.16 45.495 49.68 45.765 ;
     RECT  2.16 46.035 49.68 46.305 ;
     RECT  2.16 46.575 49.68 46.845 ;
     RECT  2.16 47.115 49.68 47.385 ;
     RECT  2.16 47.655 49.68 47.925 ;
     RECT  2.16 48.195 49.68 48.465 ;
     RECT  2.16 48.735 49.68 49.005 ;
     RECT  2.16 49.275 49.68 49.545 ;
    LAYER M1 ;
     RECT  2.16 2.151 49.68 49.689 ;
    LAYER M2 ;
     RECT  0.535 22.212 2.16 22.23 ;
     RECT  0.535 23.832 2.16 23.85 ;
     RECT  0.535 27.342 2.16 27.36 ;
     RECT  0.103 32.472 2.16 32.49 ;
     RECT  0.103 38.142 2.16 38.16 ;
     RECT  2.16 2.151 49.68 49.689 ;
     RECT  49.68 27.846 49.883 28.404 ;
     RECT  49.883 27.846 50.675 28.134 ;
     RECT  49.68 26.496 50.711 26.514 ;
     RECT  50.675 28.116 50.711 28.134 ;
     RECT  49.68 23.904 50.747 25.344 ;
     RECT  50.747 24.786 50.783 24.804 ;
    LAYER M3 ;
     RECT  23.94 0.571 23.958 1.723 ;
     RECT  25.668 0.571 25.686 1.723 ;
     RECT  22.428 1.723 29.142 2.143 ;
     RECT  22.428 2.143 29.505 2.255 ;
     RECT  22.608 2.255 29.505 2.263 ;
     RECT  2.415 2.143 2.505 2.413 ;
     RECT  7.815 2.143 7.905 2.413 ;
     RECT  13.215 2.143 13.305 2.413 ;
     RECT  18.615 2.143 18.705 2.413 ;
     RECT  34.815 2.143 34.905 2.413 ;
     RECT  40.215 2.143 40.305 2.413 ;
     RECT  45.615 2.143 45.705 2.413 ;
     RECT  22.608 2.263 29.862 2.489 ;
     RECT  22.752 2.489 29.862 2.861 ;
     RECT  22.932 2.861 29.862 3.065 ;
     RECT  23.184 3.065 29.862 3.641 ;
     RECT  23.976 3.641 29.862 3.721 ;
     RECT  23.976 3.721 30.33 3.839 ;
     RECT  23.184 3.641 23.202 3.947 ;
     RECT  24.015 3.839 30.33 4.261 ;
     RECT  24.015 4.261 30.546 4.487 ;
     RECT  2.415 2.413 2.697 10.555 ;
     RECT  2.304 10.555 2.697 10.597 ;
     RECT  2.304 10.597 3.294 10.625 ;
     RECT  2.34 10.625 3.294 10.633 ;
     RECT  4.068 10.597 4.086 10.633 ;
     RECT  2.34 10.633 4.086 10.741 ;
     RECT  7.815 2.413 8.097 11.011 ;
     RECT  2.34 10.741 4.482 11.021 ;
     RECT  2.415 11.021 4.482 11.131 ;
     RECT  5.796 11.011 5.814 11.137 ;
     RECT  18.615 2.413 18.897 11.275 ;
     RECT  5.652 11.137 5.814 11.281 ;
     RECT  18.615 11.275 18.918 11.365 ;
     RECT  5.652 11.281 5.886 11.371 ;
     RECT  17.028 11.227 17.046 11.371 ;
     RECT  18.504 11.365 18.918 11.399 ;
     RECT  18.504 11.399 18.897 11.405 ;
     RECT  2.415 11.131 4.842 11.419 ;
     RECT  5.652 11.371 6.246 11.419 ;
     RECT  2.415 11.419 6.246 11.435 ;
     RECT  2.415 11.435 4.95 11.453 ;
     RECT  5.796 11.435 6.246 11.467 ;
     RECT  17.028 11.371 17.37 11.471 ;
     RECT  5.796 11.467 6.462 11.507 ;
     RECT  7.416 11.011 8.097 11.515 ;
     RECT  17.064 11.471 17.37 11.579 ;
     RECT  5.796 11.507 6.246 11.669 ;
     RECT  7.308 11.515 8.097 11.669 ;
     RECT  3.42 11.453 4.95 11.705 ;
     RECT  17.064 11.579 17.082 11.789 ;
     RECT  2.415 11.453 2.697 11.851 ;
     RECT  7.416 11.669 8.097 11.911 ;
     RECT  7.416 11.911 8.262 11.981 ;
     RECT  9.504 11.947 9.522 12.019 ;
     RECT  25.02 4.487 30.546 12.047 ;
     RECT  9.036 12.019 9.522 12.055 ;
     RECT  5.796 11.669 6.03 12.209 ;
     RECT  8.928 12.055 9.522 12.209 ;
     RECT  5.796 12.209 5.886 12.245 ;
     RECT  3.42 11.705 4.482 12.451 ;
     RECT  2.304 11.851 2.697 12.595 ;
     RECT  3.42 12.451 4.914 12.595 ;
     RECT  2.304 12.595 4.914 12.785 ;
     RECT  2.415 12.785 4.914 12.865 ;
     RECT  2.415 12.865 5.13 13.055 ;
     RECT  3.816 13.055 5.13 13.171 ;
     RECT  5.868 12.245 5.886 13.171 ;
     RECT  3.816 13.171 5.886 13.261 ;
     RECT  7.416 11.981 8.097 13.297 ;
     RECT  9.036 12.209 9.522 13.405 ;
     RECT  3.816 13.261 6.498 13.441 ;
     RECT  7.272 13.297 8.097 13.441 ;
     RECT  3.816 13.441 8.097 13.559 ;
     RECT  7.272 13.559 8.097 13.595 ;
     RECT  3.816 13.559 6.246 13.829 ;
     RECT  14.868 13.675 14.886 13.829 ;
     RECT  3.816 13.829 6.102 13.865 ;
     RECT  2.415 13.055 2.826 14.011 ;
     RECT  15.228 13.981 15.246 14.141 ;
     RECT  2.304 14.011 2.826 14.203 ;
     RECT  3.816 13.865 5.886 14.203 ;
     RECT  2.304 14.203 5.886 14.675 ;
     RECT  3.816 14.675 5.886 14.791 ;
     RECT  3.816 14.791 6.174 14.881 ;
     RECT  7.416 13.595 8.097 14.917 ;
     RECT  2.304 14.675 2.697 14.945 ;
     RECT  3.816 14.881 6.498 15.061 ;
     RECT  7.272 14.917 8.097 15.061 ;
     RECT  3.816 15.061 8.097 15.179 ;
     RECT  7.272 15.179 8.097 15.215 ;
     RECT  7.416 15.215 8.097 15.434 ;
     RECT  8.82 13.405 9.522 15.434 ;
     RECT  2.412 14.945 2.697 15.601 ;
     RECT  3.816 15.179 6.174 15.601 ;
     RECT  2.412 15.601 6.174 15.727 ;
     RECT  2.304 15.727 6.174 16.025 ;
     RECT  3.816 16.025 6.174 16.837 ;
     RECT  7.416 15.434 9.522 16.915 ;
     RECT  3.816 16.837 6.462 16.951 ;
     RECT  7.236 16.915 9.522 16.951 ;
     RECT  3.816 16.951 9.522 17.069 ;
     RECT  2.304 16.025 2.697 17.105 ;
     RECT  2.415 17.105 2.697 17.491 ;
     RECT  2.415 17.491 2.79 17.611 ;
     RECT  3.816 17.069 6.462 17.611 ;
     RECT  2.415 17.611 6.462 18.185 ;
     RECT  2.415 18.185 2.754 18.331 ;
     RECT  2.304 18.331 2.754 18.455 ;
     RECT  7.416 17.069 8.097 18.535 ;
     RECT  3.816 18.185 6.462 18.571 ;
     RECT  7.236 18.535 8.097 18.571 ;
     RECT  3.816 18.571 8.097 18.689 ;
     RECT  2.415 18.455 2.754 18.931 ;
     RECT  3.816 18.689 6.462 18.931 ;
     RECT  2.415 18.931 6.462 19.195 ;
     RECT  2.304 19.195 6.462 19.373 ;
     RECT  2.304 19.373 6.246 19.535 ;
     RECT  7.416 18.689 8.097 20.155 ;
     RECT  3.816 19.535 6.246 20.551 ;
     RECT  7.236 20.155 8.097 20.551 ;
     RECT  3.816 20.551 8.097 20.731 ;
     RECT  8.82 17.069 9.522 20.731 ;
     RECT  3.816 20.731 9.522 20.759 ;
     RECT  3.816 20.759 6.282 21.001 ;
     RECT  2.304 19.535 2.697 21.211 ;
     RECT  3.42 21.001 6.282 21.211 ;
     RECT  2.304 21.211 6.282 21.263 ;
     RECT  2.304 21.263 2.697 21.425 ;
     RECT  3.816 21.263 6.282 21.541 ;
     RECT  7.2 20.759 9.522 21.541 ;
     RECT  3.816 21.541 9.522 21.695 ;
     RECT  4.608 21.695 9.522 21.739 ;
     RECT  0.54 22.207 0.558 22.253 ;
     RECT  2.415 21.425 2.697 22.459 ;
     RECT  3.816 21.695 3.834 22.459 ;
     RECT  4.608 21.739 9.558 22.469 ;
     RECT  2.415 22.459 3.834 22.477 ;
     RECT  4.608 22.469 6.282 22.477 ;
     RECT  2.415 22.477 6.282 22.651 ;
     RECT  2.304 22.651 6.282 22.775 ;
     RECT  3.816 22.775 6.282 23.323 ;
     RECT  7.344 22.469 9.558 23.557 ;
     RECT  2.304 22.775 2.697 23.585 ;
     RECT  3.816 23.323 6.318 23.701 ;
     RECT  7.272 23.557 9.558 23.701 ;
     RECT  49.068 23.665 49.086 23.701 ;
     RECT  49.068 23.701 49.266 23.791 ;
     RECT  3.816 23.701 9.558 23.819 ;
     RECT  7.272 23.819 9.558 23.855 ;
     RECT  3.816 23.819 6.282 23.899 ;
     RECT  48.996 23.791 49.266 23.935 ;
     RECT  48.996 23.935 49.374 23.971 ;
     RECT  0.54 23.827 0.558 23.981 ;
     RECT  48.528 23.971 49.374 24.089 ;
     RECT  48.528 24.089 49.266 24.205 ;
     RECT  25.164 12.047 30.546 24.241 ;
     RECT  47.988 24.205 49.266 24.241 ;
     RECT  25.164 24.241 30.906 24.359 ;
     RECT  2.415 23.585 2.697 24.367 ;
     RECT  47.34 24.241 49.266 24.439 ;
     RECT  2.304 24.367 2.697 24.475 ;
     RECT  3.744 23.899 6.282 24.475 ;
     RECT  45.615 2.413 45.897 24.475 ;
     RECT  47.088 24.439 49.266 24.511 ;
     RECT  45.54 24.475 45.897 24.637 ;
     RECT  47.016 24.511 49.266 24.637 ;
     RECT  45.54 24.637 49.266 24.749 ;
     RECT  50.724 23.899 50.742 24.781 ;
     RECT  2.304 24.475 6.282 25.205 ;
     RECT  44.496 25.213 44.514 25.285 ;
     RECT  3.816 25.205 6.282 25.321 ;
     RECT  44.496 25.285 44.766 25.321 ;
     RECT  2.304 25.205 3.042 25.439 ;
     RECT  3.816 25.321 6.642 25.439 ;
     RECT  50.724 24.781 50.778 25.469 ;
     RECT  25.164 24.359 30.834 25.519 ;
     RECT  38.772 25.411 38.79 25.547 ;
     RECT  44.1 25.321 44.766 25.547 ;
     RECT  7.416 23.855 9.558 25.555 ;
     RECT  43.308 25.249 43.326 25.555 ;
     RECT  43.2 25.555 43.326 25.579 ;
     RECT  44.748 25.547 44.766 25.583 ;
     RECT  45.615 24.749 49.266 25.591 ;
     RECT  42.372 25.555 42.39 25.613 ;
     RECT  43.2 25.579 43.974 25.619 ;
     RECT  3.816 25.439 6.462 25.709 ;
     RECT  7.308 25.555 9.558 25.709 ;
     RECT  25.164 25.519 31.23 25.709 ;
     RECT  43.2 25.619 43.902 25.709 ;
     RECT  45.288 25.591 49.266 25.709 ;
     RECT  43.308 25.709 43.902 25.745 ;
     RECT  50.724 25.469 50.742 25.901 ;
     RECT  33.012 25.861 33.03 25.979 ;
     RECT  2.304 25.439 2.79 26.141 ;
     RECT  45.504 25.709 48.726 26.249 ;
     RECT  2.415 26.141 2.79 26.257 ;
     RECT  3.816 25.709 6.282 26.257 ;
     RECT  45.504 26.249 47.826 26.285 ;
     RECT  25.164 25.709 30.834 26.293 ;
     RECT  25.092 26.293 30.834 26.333 ;
     RECT  48.708 26.249 48.726 26.491 ;
     RECT  45.504 26.285 47.61 26.519 ;
     RECT  48.708 26.491 49.338 26.519 ;
     RECT  50.688 26.299 50.706 26.519 ;
     RECT  45.615 26.519 47.502 26.555 ;
     RECT  49.032 26.519 49.338 26.591 ;
     RECT  45.615 26.555 46.206 26.627 ;
     RECT  34.815 2.413 35.097 26.671 ;
     RECT  2.415 26.257 6.282 26.779 ;
     RECT  2.415 26.779 6.462 26.825 ;
     RECT  2.415 26.825 2.697 26.971 ;
     RECT  34.632 26.671 35.097 27.031 ;
     RECT  2.304 26.971 2.697 27.095 ;
     RECT  43.308 25.745 43.326 27.139 ;
     RECT  7.416 25.709 9.558 27.175 ;
     RECT  43.308 27.139 43.902 27.175 ;
     RECT  3.996 26.825 6.462 27.211 ;
     RECT  7.308 27.175 9.558 27.211 ;
     RECT  49.032 26.591 49.05 27.301 ;
     RECT  43.308 27.175 44.262 27.329 ;
     RECT  43.308 27.329 43.362 27.337 ;
     RECT  42.624 27.337 43.362 27.389 ;
     RECT  0.54 27.337 0.558 27.437 ;
     RECT  34.632 27.031 35.226 27.445 ;
     RECT  41.76 27.355 41.778 27.445 ;
     RECT  42.624 27.389 43.326 27.445 ;
     RECT  41.76 27.445 43.326 27.473 ;
     RECT  47.484 26.555 47.502 27.481 ;
     RECT  48.564 27.301 49.05 27.481 ;
     RECT  49.86 26.731 49.878 27.481 ;
     RECT  50.652 27.163 50.67 27.595 ;
     RECT  34.632 27.445 35.766 27.599 ;
     RECT  41.76 27.473 42.966 27.599 ;
     RECT  45.615 26.627 46.17 27.599 ;
     RECT  41.76 27.599 41.778 27.677 ;
     RECT  3.996 27.211 9.558 27.715 ;
     RECT  42.624 27.599 42.966 27.743 ;
     RECT  18.615 11.405 18.897 27.751 ;
     RECT  47.34 27.481 47.502 27.751 ;
     RECT  48.564 27.481 49.878 27.751 ;
     RECT  2.415 27.095 2.697 27.835 ;
     RECT  3.996 27.715 10.386 27.869 ;
     RECT  18.615 27.751 19.098 27.869 ;
     RECT  42.732 27.743 42.966 27.869 ;
     RECT  50.652 27.595 50.706 27.869 ;
     RECT  3.996 27.869 5.094 27.877 ;
     RECT  47.34 27.751 49.878 27.877 ;
     RECT  2.34 27.835 2.697 27.905 ;
     RECT  3.42 27.877 5.094 27.905 ;
     RECT  5.976 27.869 10.386 27.905 ;
     RECT  42.768 27.869 42.966 27.905 ;
     RECT  47.16 27.877 49.878 27.905 ;
     RECT  47.16 27.905 47.502 27.917 ;
     RECT  5.976 27.905 6.282 27.941 ;
     RECT  47.484 27.917 47.502 27.941 ;
     RECT  2.412 27.905 2.697 28.021 ;
     RECT  3.42 27.905 5.058 28.021 ;
     RECT  50.688 27.869 50.706 28.139 ;
     RECT  48.456 27.905 49.878 28.175 ;
     RECT  49.032 28.175 49.878 28.211 ;
     RECT  2.412 28.021 5.058 28.283 ;
     RECT  49.86 28.211 49.878 28.409 ;
     RECT  49.032 28.211 49.05 28.445 ;
     RECT  18.615 27.869 18.897 28.525 ;
     RECT  2.412 28.283 2.97 28.679 ;
     RECT  5.976 27.941 6.138 28.723 ;
     RECT  3.816 28.283 5.058 28.795 ;
     RECT  5.904 28.723 6.138 28.795 ;
     RECT  5.904 28.795 6.462 28.831 ;
     RECT  7.2 27.905 10.242 28.831 ;
     RECT  3.816 28.795 5.166 28.985 ;
     RECT  3.96 28.985 5.166 29.021 ;
     RECT  4.104 29.021 5.166 29.029 ;
     RECT  5.904 28.831 10.242 29.029 ;
     RECT  2.412 28.679 2.697 29.131 ;
     RECT  18.252 28.525 18.897 29.219 ;
     RECT  20.376 27.913 20.394 29.371 ;
     RECT  2.304 29.131 2.697 29.731 ;
     RECT  2.304 29.731 3.258 29.911 ;
     RECT  4.104 29.029 10.242 29.911 ;
     RECT  2.304 29.911 10.242 30.029 ;
     RECT  2.304 30.029 4.986 30.065 ;
     RECT  18.615 29.219 18.897 30.307 ;
     RECT  2.415 30.065 4.986 30.443 ;
     RECT  18.615 30.307 18.954 30.479 ;
     RECT  4.104 30.443 4.986 30.569 ;
     RECT  5.904 30.029 10.242 30.839 ;
     RECT  7.2 30.839 10.242 30.875 ;
     RECT  2.415 30.443 3.294 31.291 ;
     RECT  2.304 31.291 3.294 31.415 ;
     RECT  4.176 30.569 4.986 31.495 ;
     RECT  2.415 31.415 3.294 31.531 ;
     RECT  4.068 31.495 4.986 31.531 ;
     RECT  2.415 31.531 4.986 31.657 ;
     RECT  5.904 30.839 6.102 31.657 ;
     RECT  2.415 31.657 6.102 31.675 ;
     RECT  2.415 31.675 6.462 31.955 ;
     RECT  2.415 31.955 2.697 32.155 ;
     RECT  32.904 26.131 32.922 32.189 ;
     RECT  7.416 30.875 10.242 32.197 ;
     RECT  2.304 32.155 2.697 32.225 ;
     RECT  5.904 31.955 6.462 32.341 ;
     RECT  7.2 32.197 10.242 32.341 ;
     RECT  5.904 32.341 10.242 32.459 ;
     RECT  7.2 32.459 10.242 32.495 ;
     RECT  0.108 32.467 0.126 32.621 ;
     RECT  2.415 32.225 2.697 33.007 ;
     RECT  2.304 33.007 2.697 33.115 ;
     RECT  3.852 31.955 4.986 33.115 ;
     RECT  5.904 32.459 6.102 33.619 ;
     RECT  2.304 33.115 4.986 33.629 ;
     RECT  3.996 33.629 4.986 33.655 ;
     RECT  5.724 33.619 6.102 33.655 ;
     RECT  3.996 33.655 6.102 33.809 ;
     RECT  3.996 33.809 4.986 33.845 ;
     RECT  2.304 33.629 2.697 34.115 ;
     RECT  7.416 32.495 10.242 34.231 ;
     RECT  19.872 29.371 20.394 34.357 ;
     RECT  7.236 34.231 10.242 34.385 ;
     RECT  7.308 34.385 10.242 34.421 ;
     RECT  5.724 33.809 6.102 34.429 ;
     RECT  7.38 34.421 10.242 34.429 ;
     RECT  14.832 34.357 14.85 34.457 ;
     RECT  7.38 34.429 10.854 34.529 ;
     RECT  2.415 34.115 2.697 34.651 ;
     RECT  4.212 33.845 4.986 34.735 ;
     RECT  19.872 34.357 20.502 34.735 ;
     RECT  2.415 34.651 3.33 34.771 ;
     RECT  4.176 34.735 4.986 34.771 ;
     RECT  2.415 34.771 4.986 34.889 ;
     RECT  2.415 34.889 3.402 35.167 ;
     RECT  4.284 34.889 4.986 35.275 ;
     RECT  5.724 34.429 6.354 35.275 ;
     RECT  7.38 34.529 9.738 35.429 ;
     RECT  7.38 35.429 9.27 35.437 ;
     RECT  4.284 35.275 6.354 35.465 ;
     RECT  4.5 35.465 6.354 35.581 ;
     RECT  7.272 35.437 9.27 35.581 ;
     RECT  2.412 35.167 3.402 35.611 ;
     RECT  2.304 35.611 3.402 35.699 ;
     RECT  4.5 35.581 9.27 35.735 ;
     RECT  19.872 34.735 20.826 36.211 ;
     RECT  21.996 30.991 22.014 36.211 ;
     RECT  14.256 36.121 14.274 36.239 ;
     RECT  18.615 30.479 18.897 36.247 ;
     RECT  14.832 36.247 14.85 36.347 ;
     RECT  18.615 36.247 18.954 36.419 ;
     RECT  5.688 35.735 9.234 36.509 ;
     RECT  2.304 35.699 2.697 36.517 ;
     RECT  4.5 35.735 4.734 36.517 ;
     RECT  2.304 36.517 3.294 36.661 ;
     RECT  4.068 36.517 4.734 36.661 ;
     RECT  5.688 36.509 6.138 36.661 ;
     RECT  25.164 26.333 30.834 36.689 ;
     RECT  5.652 36.661 6.138 36.895 ;
     RECT  2.304 36.661 4.734 36.931 ;
     RECT  5.58 36.895 6.138 36.931 ;
     RECT  2.304 36.931 6.138 36.941 ;
     RECT  2.415 36.941 6.138 37.049 ;
     RECT  2.415 37.049 3.15 37.085 ;
     RECT  3.888 37.049 6.138 37.339 ;
     RECT  2.415 37.085 2.754 37.373 ;
     RECT  7.416 36.509 9.234 37.435 ;
     RECT  3.888 37.339 6.462 37.471 ;
     RECT  7.236 37.435 9.234 37.471 ;
     RECT  3.888 37.471 9.234 37.589 ;
     RECT  25.164 36.689 30.798 37.597 ;
     RECT  32.112 32.305 32.13 37.597 ;
     RECT  3.888 37.589 6.138 37.625 ;
     RECT  25.164 37.597 32.13 37.741 ;
     RECT  2.415 37.373 2.697 37.771 ;
     RECT  7.416 37.589 9.234 37.859 ;
     RECT  2.304 37.771 2.697 37.895 ;
     RECT  25.164 37.741 32.31 37.939 ;
     RECT  3.888 37.625 4.554 38.129 ;
     RECT  7.416 37.859 8.946 38.129 ;
     RECT  2.415 37.895 2.697 38.137 ;
     RECT  3.888 38.129 4.086 38.137 ;
     RECT  42.768 27.905 42.786 38.201 ;
     RECT  0.108 38.137 0.126 38.237 ;
     RECT  2.415 38.137 4.086 38.399 ;
     RECT  2.415 38.399 3.15 38.435 ;
     RECT  3.96 38.399 4.086 38.435 ;
     RECT  2.415 38.435 2.697 38.635 ;
     RECT  25.164 37.939 32.526 38.669 ;
     RECT  5.724 37.625 6.138 38.677 ;
     RECT  5.652 38.677 6.138 38.683 ;
     RECT  2.304 38.635 2.697 38.705 ;
     RECT  10.188 38.635 10.206 38.711 ;
     RECT  4.824 38.677 4.842 38.717 ;
     RECT  5.652 38.683 6.426 38.821 ;
     RECT  7.416 38.129 8.838 38.821 ;
     RECT  10.116 38.711 10.206 38.939 ;
     RECT  25.164 38.669 32.418 38.939 ;
     RECT  3.96 38.435 3.978 38.975 ;
     RECT  4.932 38.821 6.426 38.975 ;
     RECT  19.872 36.211 22.014 39.019 ;
     RECT  7.344 38.821 8.838 39.055 ;
     RECT  5.796 38.975 6.426 39.091 ;
     RECT  7.272 39.055 8.838 39.091 ;
     RECT  5.796 39.091 8.838 39.209 ;
     RECT  10.116 38.939 10.17 39.209 ;
     RECT  4.932 38.975 4.95 39.245 ;
     RECT  10.152 39.209 10.17 39.479 ;
     RECT  2.34 38.705 2.697 39.499 ;
     RECT  19.872 39.019 22.05 39.595 ;
     RECT  34.632 27.599 35.694 39.595 ;
     RECT  27.36 38.939 32.31 39.721 ;
     RECT  7.056 39.209 8.838 39.821 ;
     RECT  5.796 39.209 6.246 39.829 ;
     RECT  27.36 39.721 32.958 39.829 ;
     RECT  25.164 38.939 26.622 39.901 ;
     RECT  27.36 39.829 32.994 39.901 ;
     RECT  5.364 39.829 6.246 40.027 ;
     RECT  7.056 39.821 8.694 40.027 ;
     RECT  2.304 39.499 2.697 40.123 ;
     RECT  4.212 39.901 4.23 40.123 ;
     RECT  5.364 40.027 8.694 40.123 ;
     RECT  4.212 40.123 8.694 40.135 ;
     RECT  2.304 40.123 3.294 40.171 ;
     RECT  4.068 40.135 8.694 40.171 ;
     RECT  34.596 39.595 35.694 40.171 ;
     RECT  25.164 39.901 32.994 40.205 ;
     RECT  2.304 40.171 8.694 40.289 ;
     RECT  27.252 40.205 32.994 40.333 ;
     RECT  33.732 40.171 35.694 40.333 ;
     RECT  4.356 40.289 8.694 40.361 ;
     RECT  2.304 40.289 3.438 40.433 ;
     RECT  2.34 40.433 3.438 40.559 ;
     RECT  4.356 40.361 5.598 40.559 ;
     RECT  2.34 40.559 3.15 40.595 ;
     RECT  4.356 40.559 4.374 40.595 ;
     RECT  5.58 40.559 5.598 40.595 ;
     RECT  6.372 40.361 8.694 40.781 ;
     RECT  6.516 40.781 8.694 40.829 ;
     RECT  27.252 40.333 35.694 41.099 ;
     RECT  25.164 40.205 26.478 41.179 ;
     RECT  27.252 41.099 32.814 41.179 ;
     RECT  2.34 40.595 2.697 41.227 ;
     RECT  2.304 41.227 2.697 41.405 ;
     RECT  25.164 41.179 32.814 41.441 ;
     RECT  33.624 41.099 35.694 41.453 ;
     RECT  5.688 41.521 5.706 41.675 ;
     RECT  7.815 40.829 8.694 41.707 ;
     RECT  25.164 41.441 32.742 41.819 ;
     RECT  13.215 2.413 13.497 42.331 ;
     RECT  7.488 41.707 8.694 42.449 ;
     RECT  25.236 41.819 32.742 42.457 ;
     RECT  25.236 42.457 33.318 42.461 ;
     RECT  7.488 42.449 8.334 42.485 ;
     RECT  28.872 42.461 33.318 42.509 ;
     RECT  13.215 42.331 14.058 42.719 ;
     RECT  7.815 42.485 8.334 42.755 ;
     RECT  19.872 39.595 22.122 42.763 ;
     RECT  19.8 42.763 22.122 42.799 ;
     RECT  25.236 42.461 27.954 42.799 ;
     RECT  34.164 41.453 35.694 42.811 ;
     RECT  33.84 42.811 35.694 42.863 ;
     RECT  19.8 42.799 22.842 42.899 ;
     RECT  25.092 42.799 27.954 42.899 ;
     RECT  18.615 36.419 18.897 43.231 ;
     RECT  28.872 42.509 33.066 43.339 ;
     RECT  18.615 43.231 19.062 43.375 ;
     RECT  19.8 42.899 22.23 43.375 ;
     RECT  28.872 43.339 33.57 43.411 ;
     RECT  25.236 42.899 27.954 43.501 ;
     RECT  28.764 43.411 33.57 43.501 ;
     RECT  15.048 39.865 15.066 43.709 ;
     RECT  25.236 43.501 33.57 43.901 ;
     RECT  25.236 43.901 33.354 44.383 ;
     RECT  13.215 42.719 13.497 44.653 ;
     RECT  13.215 44.653 13.986 44.761 ;
     RECT  14.832 44.653 14.85 44.761 ;
     RECT  24.015 4.487 24.297 44.761 ;
     RECT  25.056 44.383 33.354 44.761 ;
     RECT  34.308 42.863 35.694 44.959 ;
     RECT  7.815 42.755 8.298 44.987 ;
     RECT  13.215 44.761 14.85 44.987 ;
     RECT  34.236 44.959 35.694 44.995 ;
     RECT  24.015 44.761 33.354 45.059 ;
     RECT  14.22 44.987 14.85 45.149 ;
     RECT  14.832 45.149 14.85 45.419 ;
     RECT  34.2 44.995 35.694 45.419 ;
     RECT  18.615 43.375 22.23 45.571 ;
     RECT  25.668 45.059 33.354 45.571 ;
     RECT  34.2 45.419 35.097 45.571 ;
     RECT  16.776 44.689 16.794 45.688 ;
     RECT  16.776 45.688 17.082 45.841 ;
     RECT  18.432 45.571 22.23 46.381 ;
     RECT  25.668 45.571 35.097 46.769 ;
     RECT  18.432 46.381 22.842 46.777 ;
     RECT  25.668 46.769 32.958 46.777 ;
     RECT  16.776 45.841 17.334 46.795 ;
     RECT  18.072 46.777 22.878 46.795 ;
     RECT  16.776 46.795 22.878 46.829 ;
     RECT  33.696 46.769 33.786 46.841 ;
     RECT  24.015 45.059 24.498 46.921 ;
     RECT  25.596 46.777 32.958 46.949 ;
     RECT  24.015 46.921 24.534 46.987 ;
     RECT  25.596 46.949 30.51 46.987 ;
     RECT  24.015 46.987 30.51 47.039 ;
     RECT  33.768 46.841 33.786 47.075 ;
     RECT  24.015 47.039 26.118 47.119 ;
     RECT  17.136 46.829 22.878 47.281 ;
     RECT  23.976 47.119 26.118 47.281 ;
     RECT  36.756 47.083 36.774 47.281 ;
     RECT  17.136 47.281 26.118 47.309 ;
     RECT  34.524 46.769 35.097 47.425 ;
     RECT  36.756 47.281 36.954 47.425 ;
     RECT  36.144 47.425 36.954 47.461 ;
     RECT  34.524 47.425 35.154 47.551 ;
     RECT  31.428 46.949 32.958 47.659 ;
     RECT  36.144 47.461 37.566 47.687 ;
     RECT  31.428 47.659 32.994 47.695 ;
     RECT  27.144 47.039 30.51 47.731 ;
     RECT  31.428 47.695 33.246 47.731 ;
     RECT  17.136 47.309 26.082 47.893 ;
     RECT  27.144 47.731 33.246 47.899 ;
     RECT  34.524 47.551 35.226 47.965 ;
     RECT  36.144 47.687 36.954 47.965 ;
     RECT  27.144 47.899 33.642 48.091 ;
     RECT  34.416 47.965 36.954 48.091 ;
     RECT  15.66 48.091 15.678 48.139 ;
     RECT  27.144 48.091 36.954 48.173 ;
     RECT  14.832 48.139 15.678 48.199 ;
     RECT  14.832 48.199 15.714 48.235 ;
     RECT  16.704 47.893 26.082 48.235 ;
     RECT  14.832 48.235 26.082 48.331 ;
     RECT  27.144 48.173 35.226 48.331 ;
     RECT  14.832 48.331 35.226 48.469 ;
     RECT  14.292 48.469 35.226 48.497 ;
     RECT  36.072 48.173 36.954 48.659 ;
     RECT  14.292 48.497 14.454 48.929 ;
     RECT  14.292 48.929 14.31 48.965 ;
     RECT  15.192 48.497 35.226 48.973 ;
     RECT  36.072 48.659 36.81 48.973 ;
     RECT  15.192 48.973 36.81 49.001 ;
     RECT  2.415 41.405 2.697 49.427 ;
     RECT  7.815 44.987 8.097 49.427 ;
     RECT  13.215 44.987 13.497 49.427 ;
     RECT  40.215 2.413 40.497 49.427 ;
     RECT  45.615 27.599 45.897 49.427 ;
     RECT  15.696 49.001 36.81 49.469 ;
     RECT  15.804 49.469 26.01 49.505 ;
     RECT  15.984 49.505 26.01 49.517 ;
     RECT  26.748 49.469 36.342 49.517 ;
     RECT  32.04 49.517 32.886 49.565 ;
     RECT  34.2 49.517 36.342 49.565 ;
     RECT  15.984 49.517 16.074 49.577 ;
     RECT  16.92 49.517 24.606 49.577 ;
     RECT  26.748 49.517 28.602 49.577 ;
     RECT  30.42 49.517 30.438 49.577 ;
     RECT  31.176 49.517 31.194 49.577 ;
     RECT  32.04 49.565 32.598 49.577 ;
     RECT  34.2 49.565 35.19 49.577 ;
     RECT  36.036 49.565 36.342 49.577 ;
     RECT  2.415 49.427 2.505 49.697 ;
     RECT  7.815 49.427 7.905 49.697 ;
     RECT  13.215 49.427 13.305 49.697 ;
     RECT  23.94 49.577 24.105 49.697 ;
     RECT  29.415 49.517 29.574 49.697 ;
     RECT  34.74 49.577 34.905 49.697 ;
     RECT  40.215 49.427 40.305 49.697 ;
     RECT  45.615 49.427 45.705 49.697 ;
     RECT  18.216 49.577 18.774 49.805 ;
     RECT  29.556 49.697 29.574 49.805 ;
     RECT  23.94 49.697 23.958 49.853 ;
     RECT  34.74 49.697 34.758 49.853 ;
     RECT  26.748 49.577 27.306 50.189 ;
     RECT  18.216 49.805 18.234 50.765 ;
     RECT  22.104 49.577 22.122 50.765 ;
     RECT  25.992 49.517 26.01 50.765 ;
     RECT  26.748 50.189 26.766 50.765 ;
     RECT  36.324 49.577 36.342 50.765 ;
    LAYER M4 ;
     RECT  0.06 10.56 2.408 41.256 ;
     RECT  2.408 2.148 2.512 49.692 ;
     RECT  2.512 2.418 2.704 49.422 ;
     RECT  2.704 18.768 2.765 19.368 ;
     RECT  2.704 36.816 2.765 38.712 ;
     RECT  2.704 10.848 2.837 14.232 ;
     RECT  2.704 30.192 2.837 30.888 ;
     RECT  2.704 26.544 3.305 26.808 ;
     RECT  2.704 21.12 3.34 21.24 ;
     RECT  2.704 22.464 3.34 22.488 ;
     RECT  2.837 10.848 3.347 12.648 ;
     RECT  2.704 17.616 3.347 17.64 ;
     RECT  2.704 34.656 3.347 34.68 ;
     RECT  2.765 38.16 3.349 38.712 ;
     RECT  2.704 24.48 3.733 24.504 ;
     RECT  2.837 14.208 3.877 14.232 ;
     RECT  3.305 26.784 3.925 26.808 ;
     RECT  3.905 27.936 3.925 27.96 ;
     RECT  3.925 26.784 3.989 27.96 ;
     RECT  3.34 21.12 4.028 21.144 ;
     RECT  4.028 20.88 4.115 21.144 ;
     RECT  3.877 13.68 4.237 14.232 ;
     RECT  2.765 19.344 4.417 19.368 ;
     RECT  4.237 13.296 4.501 14.232 ;
     RECT  2.765 36.816 4.745 36.84 ;
     RECT  2.704 15.648 4.789 16.392 ;
     RECT  4.705 35.28 4.789 35.304 ;
     RECT  3.733 23.952 4.813 24.504 ;
     RECT  2.704 40.128 4.817 40.152 ;
     RECT  4.789 34.8 4.835 35.304 ;
     RECT  3.347 11.136 4.853 12.024 ;
     RECT  4.501 13.296 4.853 14.664 ;
     RECT  4.789 15.648 4.853 16.872 ;
     RECT  4.417 19.344 4.853 20.088 ;
     RECT  4.813 23.328 4.853 25.08 ;
     RECT  2.837 30.192 4.853 30.216 ;
     RECT  4.789 17.904 4.876 17.928 ;
     RECT  2.704 33.6 4.876 33.624 ;
     RECT  4.853 11.424 4.961 12.024 ;
     RECT  4.853 25.056 5.077 25.08 ;
     RECT  3.989 26.784 5.077 27.768 ;
     RECT  5.077 25.056 5.123 27.768 ;
     RECT  4.853 19.344 5.249 19.368 ;
     RECT  5.123 25.68 5.249 27.768 ;
     RECT  4.961 12 5.825 12.024 ;
     RECT  4.201 28.848 5.929 28.872 ;
     RECT  4.853 15.648 6.001 15.672 ;
     RECT  4.853 23.328 6.005 23.976 ;
     RECT  4.853 13.296 6.113 13.704 ;
     RECT  5.929 28.848 6.277 29.064 ;
     RECT  6.005 23.328 6.329 23.832 ;
     RECT  4.835 34.8 6.365 34.824 ;
     RECT  3.349 38.688 6.373 38.712 ;
     RECT  6.332 40.752 6.373 40.776 ;
     RECT  4.849 21.648 6.397 21.672 ;
     RECT  6.373 40.752 6.419 41.736 ;
     RECT  6.373 38.688 6.421 39.768 ;
     RECT  4.669 31.872 6.431 31.896 ;
     RECT  6.001 11.952 6.433 11.976 ;
     RECT  6.277 28.848 6.433 29.784 ;
     RECT  6.431 31.68 6.433 31.896 ;
     RECT  6.397 21.648 6.437 21.816 ;
     RECT  6.421 38.448 6.46 39.768 ;
     RECT  6.001 15.648 6.469 15.72 ;
     RECT  4.853 16.848 6.473 16.872 ;
     RECT  5.249 25.68 6.473 25.704 ;
     RECT  5.249 26.784 6.473 27.768 ;
     RECT  6.433 28.848 6.473 31.896 ;
     RECT  6.46 38.448 6.501 38.712 ;
     RECT  6.421 37.344 6.508 37.368 ;
     RECT  6.473 30.72 6.517 31.704 ;
     RECT  6.473 28.896 6.545 28.92 ;
     RECT  6.473 27.12 6.581 27.768 ;
     RECT  6.46 39.744 7.513 39.768 ;
     RECT  6.517 31.68 7.669 31.704 ;
     RECT  7.585 28.512 7.765 28.536 ;
     RECT  6.433 11.472 7.808 11.976 ;
     RECT  6.113 13.296 7.808 13.56 ;
     RECT  6.469 14.928 7.808 15.72 ;
     RECT  6.433 19.008 7.808 19.032 ;
     RECT  6.437 21.792 7.808 21.816 ;
     RECT  6.329 23.808 7.808 23.832 ;
     RECT  7.477 26.064 7.808 26.088 ;
     RECT  6.581 27.12 7.808 27.144 ;
     RECT  7.765 28.176 7.808 28.536 ;
     RECT  7.669 30.672 7.808 32.52 ;
     RECT  6.325 36 7.808 36.024 ;
     RECT  6.501 38.448 7.808 38.472 ;
     RECT  7.513 39.744 7.808 40.44 ;
     RECT  6.419 41.712 7.808 41.736 ;
     RECT  7.808 2.148 7.912 49.692 ;
     RECT  7.912 2.418 8.104 49.422 ;
     RECT  8.104 11.472 8.243 11.976 ;
     RECT  8.104 13.632 8.243 15.576 ;
     RECT  8.104 21.072 8.243 22.248 ;
     RECT  8.104 23.952 8.243 23.976 ;
     RECT  8.104 26.064 8.243 26.088 ;
     RECT  8.104 30.672 8.243 30.696 ;
     RECT  8.243 21.072 8.245 21.096 ;
     RECT  8.104 38.016 8.245 38.664 ;
     RECT  8.243 11.76 8.273 11.976 ;
     RECT  8.243 15.552 8.273 15.576 ;
     RECT  8.104 27.12 8.281 29.4 ;
     RECT  8.104 36.144 8.525 36.456 ;
     RECT  8.281 27.12 8.705 28.536 ;
     RECT  8.705 27.12 9.685 27.144 ;
     RECT  8.245 38.64 9.685 38.664 ;
     RECT  9.685 26.304 9.731 27.144 ;
     RECT  8.525 36.432 9.731 36.456 ;
     RECT  8.705 28.512 10.163 28.536 ;
     RECT  9.685 38.64 10.181 39.432 ;
     RECT  10.181 38.64 10.217 38.664 ;
     RECT  8.273 11.76 13.208 11.784 ;
     RECT  8.243 14.112 13.208 14.136 ;
     RECT  9.731 26.304 13.208 26.328 ;
     RECT  13.208 2.148 13.312 49.692 ;
     RECT  13.312 2.418 13.504 49.422 ;
     RECT  13.504 14.112 14.857 14.136 ;
     RECT  13.504 44.976 15.251 45 ;
     RECT  14.857 13.68 15.257 14.136 ;
     RECT  14.821 48.144 15.289 48.168 ;
     RECT  13.504 26.304 15.301 26.328 ;
     RECT  15.289 48.144 15.329 48.456 ;
     RECT  13.504 11.76 15.349 11.784 ;
     RECT  15.257 13.68 15.395 13.704 ;
     RECT  15.329 48.432 15.692 48.456 ;
     RECT  15.692 48.432 15.779 49.032 ;
     RECT  16.045 49.488 16.697 49.56 ;
     RECT  15.349 11.376 17.017 11.784 ;
     RECT  17.017 11.232 17.093 11.784 ;
     RECT  18.205 50.736 18.371 50.76 ;
     RECT  15.779 48.432 18.457 48.456 ;
     RECT  17.093 11.232 18.608 11.4 ;
     RECT  15.301 26.304 18.608 26.568 ;
     RECT  17.053 45.696 18.608 45.72 ;
     RECT  16.765 46.8 18.608 46.824 ;
     RECT  18.457 47.904 18.608 48.456 ;
     RECT  16.697 49.536 18.608 49.56 ;
     RECT  18.608 2.148 18.712 49.692 ;
     RECT  18.712 2.418 18.716 49.692 ;
     RECT  18.716 2.418 18.803 49.8 ;
     RECT  18.803 2.418 18.904 49.56 ;
     RECT  18.904 43.296 19.043 43.32 ;
     RECT  18.904 46.896 19.325 48.456 ;
     RECT  19.325 46.896 19.865 47.928 ;
     RECT  18.904 44.448 20.113 44.472 ;
     RECT  20.113 44.112 20.153 44.472 ;
     RECT  18.904 45.696 20.545 45.72 ;
     RECT  20.545 45.552 20.725 45.72 ;
     RECT  20.725 45.552 20.771 45.816 ;
     RECT  20.771 45.696 20.789 45.816 ;
     RECT  19.865 46.896 20.789 47.64 ;
     RECT  20.789 45.696 20.833 47.64 ;
     RECT  20.833 45.696 20.867 48.312 ;
     RECT  20.867 46.752 20.873 48.312 ;
     RECT  20.153 44.112 20.908 44.424 ;
     RECT  20.908 44.112 21.197 44.184 ;
     RECT  20.873 46.848 21.485 48.312 ;
     RECT  21.485 46.848 21.881 47.64 ;
     RECT  21.881 46.896 22.133 47.64 ;
     RECT  22.093 50.736 22.259 50.76 ;
     RECT  18.904 11.28 22.499 11.4 ;
     RECT  22.453 3.696 22.7 3.72 ;
     RECT  22.7 2.832 22.787 3.72 ;
     RECT  22.133 47.088 23.857 47.112 ;
     RECT  22.453 48.096 23.857 48.12 ;
     RECT  22.499 11.376 23.893 11.4 ;
     RECT  18.904 49.536 23.9 49.56 ;
     RECT  23.9 49.536 23.987 49.848 ;
     RECT  22.417 1.728 24.008 1.752 ;
     RECT  22.787 3.696 24.008 3.72 ;
     RECT  23.893 11.232 24.008 11.4 ;
     RECT  18.904 26.304 24.008 26.568 ;
     RECT  21.197 44.16 24.008 44.184 ;
     RECT  20.867 45.696 24.008 45.72 ;
     RECT  23.857 47.088 24.008 48.12 ;
     RECT  23.987 49.536 24.008 49.692 ;
     RECT  23.929 0.576 24.013 0.6 ;
     RECT  24.008 1.728 24.112 49.692 ;
     RECT  24.112 1.728 24.304 49.56 ;
     RECT  24.304 49.488 24.851 49.56 ;
     RECT  24.304 26.304 25.265 26.568 ;
     RECT  24.304 44.16 25.481 45.72 ;
     RECT  24.304 46.992 25.585 47.928 ;
     RECT  25.513 42.576 25.621 42.6 ;
     RECT  25.481 44.16 25.621 44.424 ;
     RECT  24.304 2.88 25.669 2.904 ;
     RECT  24.304 3.984 25.669 4.008 ;
     RECT  25.621 42.576 25.669 44.424 ;
     RECT  25.657 0.576 25.741 0.6 ;
     RECT  24.851 49.488 25.769 49.512 ;
     RECT  25.669 39.552 25.805 39.576 ;
     RECT  25.669 42.096 25.949 44.424 ;
     RECT  24.304 11.232 26.125 11.256 ;
     RECT  26.125 11.136 26.165 11.256 ;
     RECT  26.101 49.344 26.201 49.368 ;
     RECT  25.669 2.88 26.273 4.008 ;
     RECT  26.273 2.88 26.305 3.96 ;
     RECT  26.305 2.832 26.309 3.96 ;
     RECT  26.309 2.832 26.389 2.856 ;
     RECT  25.481 45.6 26.413 45.72 ;
     RECT  25.585 46.8 26.413 47.928 ;
     RECT  26.341 40.176 26.597 40.2 ;
     RECT  26.413 45.6 26.665 47.928 ;
     RECT  25.949 43.008 26.771 44.424 ;
     RECT  26.665 45.6 26.771 48.36 ;
     RECT  26.771 44.064 26.809 44.424 ;
     RECT  25.981 50.736 27.011 50.76 ;
     RECT  26.809 44.064 27.173 44.616 ;
     RECT  26.3 41.376 27.277 41.928 ;
     RECT  26.165 11.136 27.349 11.16 ;
     RECT  27.277 50.16 27.443 50.184 ;
     RECT  26.309 3.936 27.493 3.96 ;
     RECT  27.493 3.936 27.587 4.248 ;
     RECT  27.349 10.848 27.587 11.16 ;
     RECT  27.277 41.232 27.731 41.928 ;
     RECT  27.457 38.448 27.749 38.472 ;
     RECT  27.685 40.176 27.772 40.2 ;
     RECT  27.731 41.28 27.889 41.928 ;
     RECT  27.173 44.064 27.925 44.424 ;
     RECT  27.025 37.056 28.076 37.08 ;
     RECT  28.076 37.056 28.163 37.992 ;
     RECT  28.163 37.056 28.253 37.656 ;
     RECT  25.585 26.256 28.357 26.28 ;
     RECT  26.771 45.6 28.357 47.352 ;
     RECT  28.357 45.6 28.361 47.688 ;
     RECT  27.587 11.136 28.403 11.16 ;
     RECT  28.316 13.296 28.403 13.32 ;
     RECT  28.357 26.256 28.403 26.76 ;
     RECT  27.925 43.92 28.717 44.424 ;
     RECT  28.717 43.92 29.077 44.952 ;
     RECT  27.709 49.536 29.125 49.56 ;
     RECT  24.304 1.728 29.197 1.752 ;
     RECT  29.077 39.984 29.208 40.008 ;
     RECT  27.889 41.28 29.208 42.456 ;
     RECT  27.587 3.936 29.221 3.96 ;
     RECT  29.125 2.832 29.408 2.856 ;
     RECT  29.221 3.936 29.408 4.248 ;
     RECT  29.041 13.248 29.408 13.272 ;
     RECT  29.269 25.488 29.408 25.512 ;
     RECT  28.403 26.736 29.408 26.76 ;
     RECT  28.253 37.632 29.408 37.656 ;
     RECT  29.208 39.984 29.408 42.456 ;
     RECT  29.077 43.536 29.408 44.952 ;
     RECT  28.361 46.032 29.408 47.688 ;
     RECT  29.125 49.488 29.408 49.56 ;
     RECT  29.408 2.148 29.512 49.692 ;
     RECT  29.512 2.418 29.516 49.692 ;
     RECT  29.516 2.418 29.603 49.8 ;
     RECT  29.603 2.418 29.704 49.56 ;
     RECT  29.704 25.488 29.801 25.608 ;
     RECT  29.704 43.344 29.843 47.544 ;
     RECT  29.704 38.784 29.981 41.976 ;
     RECT  29.843 43.344 30.089 45.528 ;
     RECT  29.843 46.608 30.161 47.544 ;
     RECT  30.089 43.92 30.227 45.528 ;
     RECT  30.227 44.64 30.269 44.664 ;
     RECT  29.981 38.928 30.593 41.976 ;
     RECT  30.593 39.792 30.733 41.976 ;
     RECT  29.704 37.632 30.773 37.656 ;
     RECT  30.733 39.792 30.809 42.84 ;
     RECT  30.809 40.608 31.129 42.84 ;
     RECT  30.161 46.608 31.417 47.112 ;
     RECT  31.129 40.608 31.601 42.936 ;
     RECT  29.704 49.488 31.817 49.56 ;
     RECT  31.601 40.608 32.044 42.504 ;
     RECT  32.425 43.92 32.497 43.944 ;
     RECT  32.044 41.952 32.579 42.504 ;
     RECT  31.417 46.608 32.677 47.352 ;
     RECT  31.817 49.536 33.059 49.56 ;
     RECT  32.044 40.608 33.301 40.632 ;
     RECT  32.579 42.48 33.301 42.504 ;
     RECT  32.497 43.92 33.301 44.472 ;
     RECT  33.301 42.48 33.347 44.472 ;
     RECT  33.347 42.72 33.539 44.472 ;
     RECT  33.539 42.72 33.581 43.896 ;
     RECT  33.301 40.608 33.653 41.448 ;
     RECT  32.677 46.608 33.653 47.928 ;
     RECT  33.653 46.608 33.725 47.112 ;
     RECT  33.445 49.488 34.189 49.512 ;
     RECT  34.189 45.6 34.213 45.624 ;
     RECT  33.653 40.608 34.225 40.92 ;
     RECT  34.225 40.464 34.585 40.92 ;
     RECT  34.189 49.488 34.7 49.56 ;
     RECT  34.7 49.488 34.787 49.848 ;
     RECT  29.801 25.584 34.808 25.608 ;
     RECT  34.585 39.6 34.808 40.92 ;
     RECT  33.581 42.72 34.808 42.84 ;
     RECT  34.213 44.976 34.808 45.624 ;
     RECT  33.725 47.088 34.808 47.112 ;
     RECT  34.405 48.144 34.808 48.168 ;
     RECT  34.787 49.488 34.808 49.692 ;
     RECT  34.808 2.148 34.912 49.692 ;
     RECT  34.912 2.418 35.104 49.56 ;
     RECT  35.104 39.6 35.219 39.624 ;
     RECT  35.104 48.144 35.741 48.168 ;
     RECT  35.104 49.536 36.083 49.56 ;
     RECT  36.313 50.736 36.515 50.76 ;
     RECT  35.104 47.088 36.785 47.112 ;
     RECT  35.104 25.584 40.208 25.608 ;
     RECT  35.104 27.648 40.208 27.672 ;
     RECT  40.208 2.148 40.312 49.692 ;
     RECT  40.312 2.418 40.504 49.422 ;
     RECT  40.504 27.648 41.749 27.672 ;
     RECT  41.749 27.36 41.789 27.672 ;
     RECT  41.789 27.36 43.861 27.384 ;
     RECT  43.861 27.36 43.907 27.912 ;
     RECT  40.504 25.584 45.493 25.608 ;
     RECT  45.493 24.72 45.529 26.28 ;
     RECT  45.529 24.48 45.608 26.28 ;
     RECT  43.907 27.888 45.608 27.912 ;
     RECT  45.608 2.148 45.712 49.692 ;
     RECT  45.712 2.418 45.904 49.422 ;
     RECT  45.904 26.064 46.541 26.088 ;
     RECT  45.904 24.48 47.189 24.504 ;
     RECT  45.904 27.888 47.189 27.912 ;
     RECT  49.849 26.736 50.641 26.76 ;
     RECT  50.641 26.736 50.677 27.192 ;
     RECT  49.237 24.576 50.713 24.6 ;
     RECT  50.677 26.304 50.713 27.624 ;
     RECT  50.713 24.144 51.804 27.624 ;
    LAYER M5 ;
     RECT  22.656 0.016 29.16 1.763 ;
     RECT  2.4 2.137 2.52 2.151 ;
     RECT  7.8 2.137 7.92 2.151 ;
     RECT  13.2 2.137 13.32 2.151 ;
     RECT  18.6 2.137 18.72 2.151 ;
     RECT  29.4 2.137 29.52 2.151 ;
     RECT  34.8 2.137 34.92 2.151 ;
     RECT  40.2 2.137 40.32 2.151 ;
     RECT  45.6 2.137 45.72 2.151 ;
     RECT  29.4 2.151 29.712 2.821 ;
     RECT  26.352 2.821 26.376 3.301 ;
     RECT  22.752 2.821 22.776 3.685 ;
     RECT  22.464 3.685 22.776 3.731 ;
     RECT  2.4 2.151 2.712 10.837 ;
     RECT  27.552 4.213 27.576 10.883 ;
     RECT  29.136 2.821 29.712 11.125 ;
     RECT  24 1.763 24.312 11.221 ;
     RECT  22.464 3.731 22.488 11.315 ;
     RECT  23.904 11.221 24.312 11.411 ;
     RECT  7.8 2.151 8.112 11.461 ;
     RECT  7.8 11.461 8.232 11.795 ;
     RECT  7.8 11.795 8.112 13.621 ;
     RECT  15.36 11.365 15.384 13.715 ;
     RECT  4.512 13.285 4.536 14.675 ;
     RECT  7.8 13.621 8.232 15.491 ;
     RECT  2.4 10.837 3.336 17.651 ;
     RECT  4.8 16.357 4.824 17.939 ;
     RECT  2.4 17.651 2.712 19.333 ;
     RECT  7.8 15.491 8.112 21.061 ;
     RECT  7.8 21.061 8.232 22.259 ;
     RECT  2.4 19.333 4.104 22.499 ;
     RECT  6.288 21.637 6.312 23.363 ;
     RECT  7.8 22.259 8.112 23.941 ;
     RECT  45.6 2.151 45.912 24.709 ;
     RECT  45.504 24.709 45.912 26.291 ;
     RECT  28.368 11.125 29.712 26.771 ;
     RECT  5.088 25.045 5.112 26.819 ;
     RECT  4.08 22.499 4.104 27.155 ;
     RECT  34.8 2.151 35.112 27.637 ;
     RECT  7.8 23.941 8.232 27.923 ;
     RECT  43.872 27.349 43.896 27.923 ;
     RECT  3.936 27.301 3.96 27.971 ;
     RECT  9.696 26.293 9.72 28.501 ;
     RECT  9.696 28.501 10.152 28.547 ;
     RECT  7.8 27.923 8.112 29.365 ;
     RECT  6.288 29.029 6.312 29.795 ;
     RECT  4.56 28.837 4.584 30.227 ;
     RECT  7.8 29.365 8.232 30.661 ;
     RECT  7.68 30.661 8.232 30.707 ;
     RECT  6.48 30.709 6.504 31.715 ;
     RECT  7.68 30.707 8.112 32.531 ;
     RECT  2.4 22.499 2.712 33.589 ;
     RECT  2.4 33.589 3.336 34.691 ;
     RECT  4.8 33.589 4.824 35.315 ;
     RECT  10.128 28.547 10.152 36.421 ;
     RECT  6.432 35.989 6.456 37.379 ;
     RECT  28.128 37.045 28.152 37.621 ;
     RECT  29.136 26.771 29.712 37.621 ;
     RECT  28.128 37.621 29.712 38.003 ;
     RECT  7.8 32.531 8.112 38.005 ;
     RECT  2.4 34.691 2.712 38.149 ;
     RECT  7.8 38.005 8.232 38.675 ;
     RECT  6.432 38.437 6.456 38.723 ;
     RECT  9.696 36.421 10.152 38.771 ;
     RECT  9.696 38.771 9.72 39.443 ;
     RECT  34.8 27.637 35.208 39.635 ;
     RECT  2.4 38.149 3.336 40.163 ;
     RECT  29.088 38.003 29.712 40.981 ;
     RECT  29.088 40.981 30.072 41.269 ;
     RECT  27.696 40.165 27.72 41.411 ;
     RECT  6.384 39.061 6.408 41.747 ;
     RECT  31.968 41.509 31.992 41.941 ;
     RECT  33.312 40.933 33.336 41.941 ;
     RECT  31.968 41.941 33.336 41.987 ;
     RECT  32.544 41.987 33.336 42.515 ;
     RECT  25.68 3.301 26.376 42.997 ;
     RECT  18.6 2.151 18.912 43.285 ;
     RECT  32.64 42.515 33.336 43.861 ;
     RECT  25.68 42.997 26.76 44.435 ;
     RECT  18.6 43.285 19.032 44.483 ;
     RECT  32.64 43.861 33.528 44.483 ;
     RECT  29.088 41.269 30.936 44.675 ;
     RECT  15.312 26.533 15.336 44.965 ;
     RECT  34.8 39.635 35.112 44.965 ;
     RECT  20.832 44.389 20.856 45.541 ;
     RECT  26.352 44.435 26.76 45.635 ;
     RECT  34.224 44.965 35.112 45.635 ;
     RECT  20.736 45.541 20.856 45.827 ;
     RECT  29.28 44.675 30.936 46.643 ;
     RECT  20.832 45.827 20.856 46.787 ;
     RECT  30.912 46.643 30.936 46.883 ;
     RECT  29.4 46.643 29.832 47.555 ;
     RECT  15.216 44.965 15.336 48.179 ;
     RECT  26.736 45.635 26.76 48.371 ;
     RECT  15.312 48.179 15.336 48.997 ;
     RECT  15.312 48.997 15.768 49.477 ;
     RECT  24 11.411 24.312 49.477 ;
     RECT  26.112 49.333 26.136 49.477 ;
     RECT  29.4 47.555 29.712 49.477 ;
     RECT  34.8 45.635 35.112 49.477 ;
     RECT  15.312 49.477 16.632 49.525 ;
     RECT  18.6 44.483 18.912 49.525 ;
     RECT  24 49.477 26.136 49.525 ;
     RECT  29.136 49.477 31.752 49.525 ;
     RECT  33.456 49.477 35.112 49.525 ;
     RECT  2.4 40.163 2.712 49.689 ;
     RECT  7.8 38.675 8.112 49.689 ;
     RECT  13.2 2.151 13.512 49.689 ;
     RECT  40.2 2.151 40.512 49.689 ;
     RECT  45.6 26.291 45.912 49.689 ;
     RECT  2.4 49.689 2.52 49.703 ;
     RECT  7.8 49.689 7.92 49.703 ;
     RECT  13.2 49.689 13.32 49.703 ;
     RECT  40.2 49.689 40.32 49.703 ;
     RECT  45.6 49.689 45.72 49.703 ;
     RECT  27.84 49.525 36.072 50.149 ;
     RECT  15.312 49.525 26.136 50.725 ;
     RECT  27.408 50.149 36.072 50.725 ;
     RECT  15.312 50.725 36.504 51.792 ;
     RECT  22.752 1.763 24 2.821 ;
     RECT  26.352 1.763 26.376 2.821 ;
     RECT  29.136 1.763 29.16 2.137 ;
     RECT  29.136 2.137 29.4 2.821 ;
     RECT  22.776 2.821 24 3.731 ;
     RECT  24.312 3.301 25.68 44.435 ;
     RECT  22.488 3.731 24 11.221 ;
     RECT  26.376 4.213 27.552 10.883 ;
     RECT  22.488 11.221 23.904 11.315 ;
     RECT  3.336 13.285 4.512 14.675 ;
     RECT  3.336 16.357 4.8 17.651 ;
     RECT  6.312 21.637 7.8 23.363 ;
     RECT  2.712 22.499 4.08 27.155 ;
     RECT  4.104 25.045 5.088 26.819 ;
     RECT  8.232 26.293 9.696 27.923 ;
     RECT  2.712 27.155 3.96 27.301 ;
     RECT  2.712 27.301 3.936 27.971 ;
     RECT  8.112 27.923 9.696 28.547 ;
     RECT  8.112 28.547 8.232 29.365 ;
     RECT  6.312 29.029 7.8 29.795 ;
     RECT  6.48 29.795 7.8 30.661 ;
     RECT  6.48 30.661 7.68 30.709 ;
     RECT  6.504 30.709 7.68 31.715 ;
     RECT  3.336 33.589 4.8 34.691 ;
     RECT  6.456 35.989 7.8 37.379 ;
     RECT  28.152 37.045 29.136 37.621 ;
     RECT  6.432 37.379 7.8 38.437 ;
     RECT  8.232 38.005 9.696 38.675 ;
     RECT  6.456 38.437 7.8 38.723 ;
     RECT  6.432 38.723 7.8 39.061 ;
     RECT  6.408 39.061 7.8 41.747 ;
     RECT  26.376 40.165 27.696 41.411 ;
     RECT  27.72 40.165 29.088 41.411 ;
     RECT  33.336 40.933 34.8 43.861 ;
     RECT  30.936 41.509 31.968 41.987 ;
     RECT  31.992 41.509 33.312 41.941 ;
     RECT  33.528 43.861 34.8 44.483 ;
     RECT  34.224 44.483 34.8 44.965 ;
     RECT  29.832 46.643 30.912 46.883 ;
     RECT  26.136 50.149 27.408 50.725 ;
  END
END dsfd_vm_static_read_v2_p
END LIBRARY
